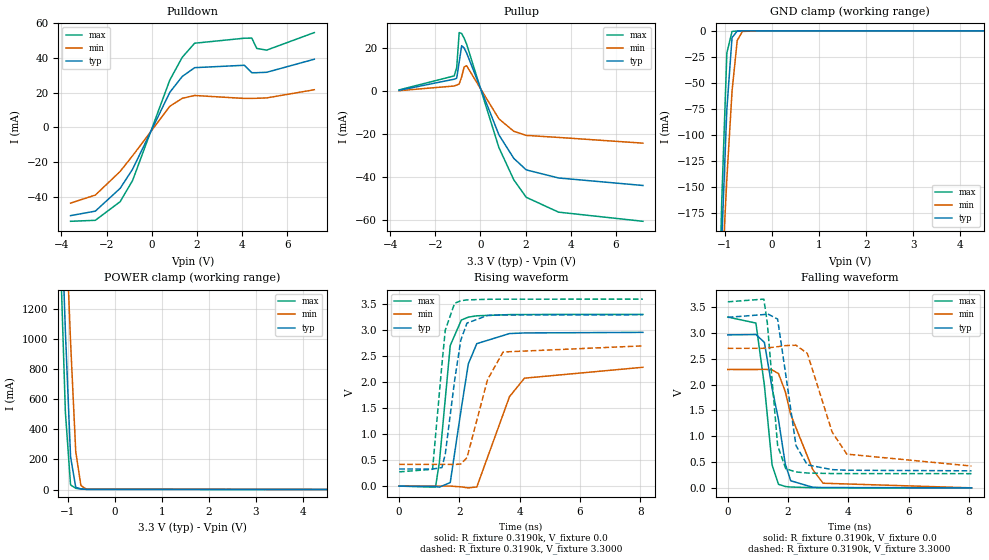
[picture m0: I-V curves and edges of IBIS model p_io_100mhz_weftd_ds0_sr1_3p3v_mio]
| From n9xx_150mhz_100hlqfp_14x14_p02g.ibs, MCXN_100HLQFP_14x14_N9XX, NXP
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[Model] p_io_100mhz_weftd_ds0_sr1_3p3v_mio
|   Model p_io_100mhz_weftd_ds0_sr1_3p3v_mio
| This model was characterised for following simulation conditions:
| External (pad) voltage:
|   - Typ: 3.3V,   - Min: 2.7V,   - Max: 3.6V
| Library cells for typ/min/max conditions are connected as defined below:
|  pad - External Pad
|  ipp_do_lv - Core Input
|  ipp_obe_lv - Output Buffer Enable
|  IOGC - NC
|  REFH3V3 - REFH3V3
|  REFL3V3 - REFL3V3
|  ZI - NC
|  abut_ncal_vddio[1] - vddio
|  abut_ncal_vddio[2] - vddio
|  abut_ncal_vddio[3] - vssio
|  abut_ncal_vddio[4] - vddio
|  abut_ncal_vddio[5] - vddio
|  abut_ncal_vddio[6] - vssio
|  abut_pcal_vddio[1] - vssio
|  abut_pcal_vddio[2] - vssio
|  abut_pcal_vddio[3] - vddio
|  abut_pcal_vddio[4] - vssio
|  abut_pcal_vddio[5] - vssio
|  abut_pcal_vddio[6] - vddio
|  ipp_do_1p8v - ipp_do_1p8v
|  ipp_dse_lv - 0
|  ipp_eftd_lv - NC
|  ipp_ina_mux_vddio - NC
|  ipp_ina_mux_vddio[0] - NC
|  ipp_ina_mux_vddio[1] - NC
|  ipp_ina_r0_vddio - NC
|  ipp_ina_r0a_vddio - NC
|  ipp_ina_r0b_vddio - NC
|  ipp_ina_r0c_vddio - NC
|  ipp_ina_r0d_vddio - NC
|  ipp_ina_r0e_vddio - NC
|  ipp_ina_r0f_vddio - NC
|  ipp_ina_r300_vddio - NC
|  ipp_ina_r300a_vddio - NC
|  ipp_ina_r300b_vddio - NC
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Model_type I/O
Polarity   Non-Inverting
Enable   Active-High
Vinl =   0.9900V
Vinh =   2.3100V
Vmeas =  1.6500V
Cref =   30.0000pF
Rref =   1.0000M
Vref =   3.3000V
C_comp   1.3824pF   1.3233pF   1.4661pF
|C_comp_pullup   0.6932pF   0.7246pF   0.6714pF
|C_comp_pulldown   0.6082pF   0.6609pF   0.5701pF
[Model Spec]
| variable   typ   min   max
Vinh   2.3100V   1.8900V   2.5200V
Vinl   0.9900V   0.8100V   1.0800V
[Temperature Range]   25.0000   0.1250k   -40.0000
[Voltage Range]   3.3000V   2.7000V   3.6000V
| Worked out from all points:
|   slope of the pulldown table from 0 to 0.495 V, typ, clamps not added: 36.8 ohm
|   slope of the pullup table from 0 to 0.495 V, typ, clamps not added: 37.8 ohm
|   GND clamp passes 1 mA (typ) near -0.75 V on its own axis
|   POWER clamp passes 1 mA (typ) near -0.55 V on its own axis
|   rising waveform, R_fixture 0.3190k, V_fixture 0.0: 20-80 % time 437ps typ, 779ps min, 310ps max; typ from 0 V to 2.96 V
|   rising waveform, R_fixture 0.3190k, V_fixture 3.3000: 20-80 % time 419ps typ, 681ps min, 295ps max; typ from 0.33 V to 3.3 V
|   falling waveform, R_fixture 0.3190k, V_fixture 0.0: 20-80 % time 516ps typ, 821ps min, 360ps max; typ from 2.96 V to 0 V
|   falling waveform, R_fixture 0.3190k, V_fixture 3.3000: 20-80 % time 404ps typ, 755ps min, 278ps max; typ from 3.3 V to 0.33 V
[Pulldown]
|Voltage   I(typ)   I(min)   I(max)
-3.6V     -50.99mA   -43.76mA   -54.26mA
-2.5V     -48.39mA   -39.11mA   -53.69mA
-1.4V     -35.22mA   -25.46mA   -42.92mA
-850mV    -24.19mA   -16.4mA    -30.7mA
800mV     20.23mA    12.14mA    27.32mA
1.35V     29.37mA    16.76mA    40.44mA
1.9V      34.45mA    18.38mA    48.57mA
4.1V      35.83mA    16.68mA    51.45mA
4.43V     31.54mA    16.72mA    51.52mA
4.65V     31.54mA    16.77mA    45.56mA
5.09V     31.78mA    16.98mA    44.58mA
7.2V      39.32mA    21.7mA     54.71mA
[Pullup]
|Voltage   I(typ)   I(min)   I(max)
-3.6V     392.3uA    235.2uA    607.2uA
-1.16V    5.571mA    2.41mA     7.094mA
-1.05V    6.017mA    2.857mA    10.99mA
-940mV    13.55mA    3.321mA    27.21mA
-830mV    21.12mA    6.673mA    26.77mA
-720mV    20.02mA    11.25mA    24.57mA
-610mV    17.72mA    11.8mA     21.82mA
820mV     -20.27mA   -12.85mA   -26.19mA
1.48V     -31.2mA    -18.62mA   -41.17mA
2.03V     -36.53mA   -20.52mA   -49.25mA
3.46V     -40.29mA   -21.47mA   -56.15mA
7.2V      -43.77mA   -24.12mA   -60.4mA
[GND_clamp]
|Voltage   I(typ)   I(min)   I(max)
-3.6V     -4.179A    -3.084A    -5.65A
-1.18V    -350.3mA   -344.8mA   -366.5mA
-1.07V    -203.5mA   -240.3mA   -165.6mA
-960mV    -75.17mA   -142.1mA   -21.27mA
-850mV    -6.53mA    -58.02mA   -538.4uA
-740mV    -289.9uA   -9.332mA   -209.1uA
-630mV    -85.04uA   -601.4uA   -92.54uA
-300mV    -199.1nA   -1.25uA    -48.79nA
7.2V      0A         0A         0A
[POWER_clamp]
|Voltage   I(typ)   I(min)   I(max)
-3.6V     24.55A     22.33A     26.93A
-1.16V    2.047A     2.721A     1.599A
-1.05V    1.052A     1.848A     514.6mA
-940mV    218.8mA    982.2mA    31.26mA
-830mV    15.16mA    252.6mA    8.517mA
-720mV    4.307mA    26.88mA    4.483mA
-610mV    1.728mA    3.641mA    1.672mA
7.2V      0A         0A         0A
[Ramp]
| variable   typ   min   max
dV/dt_r  1.7760/0.4371n   1.3726/0.7786n   1.9829/0.3104n
dV/dt_f  1.7821/0.4037n   1.3666/0.7552n   1.9953/0.2777n
R_load = 0.3190k
[Rising Waveform]
R_fixture= 0.3190k
V_fixture= 0.0
V_fixture_min= 0.0
V_fixture_max= 0.0
|time   V(typ)   V(min)   V(max)
0s        3.011nV    251.5nV    9.8nV
1.206ns   -7.511mV   -184.4uV   -19.56mV
1.335ns   -19.5mV    138.1uV    456.6mV
1.696ns   68.92mV    544.4uV    2.707V
2.064ns   1.5V       -15.61mV   3.197V
2.296ns   2.353V     -33.63mV   3.253V
2.577ns   2.743V     -16.96mV   3.279V
3.662ns   2.937V     1.722V     3.302V
4.157ns   2.949V     2.078V     3.304V
8.09ns    2.96V      2.288V     3.305V
[Rising Waveform]
R_fixture= 0.3190k
V_fixture= 3.3000
V_fixture_min= 2.7000
V_fixture_max= 3.6000
|time   V(typ)   V(min)   V(max)
0s        329.6mV    418.3mV    274.4mV
1.109ns   328.4mV    418.1mV    323.9mV
1.421ns   356.6mV    418.8mV    2.35V
1.531ns   616.8mV    419.3mV    3.003V
1.84ns    2.031V     415.3mV    3.519V
2.046ns   2.81V      426.1mV    3.569V
2.251ns   3.138V     546.9mV    3.585V
2.934ns   3.286V     2.051V     3.597V
3.449ns   3.295V     2.582V     3.599V
8.09ns    3.3V       2.7V       3.6V
[Falling Waveform]
R_fixture= 0.3190k
V_fixture= 0.0
V_fixture_min= 0.0
V_fixture_max= 0.0
|time   V(typ)   V(min)   V(max)
0s        2.96V      2.291V     3.305V
933.9ps   2.967V     2.29V      3.189V
1.215ns   2.816V     2.294V     1.987V
1.472ns   1.926V     2.283V     440.3mV
1.683ns   1.32V      2.211V     68.58mV
1.909ns   460.8mV    1.863V     26.48mV
2.089ns   136.9mV    1.417V     16.07mV
2.819ns   11.95mV    356mV      3.255mV
3.162ns   6.365mV    89.73mV    1.766mV
8.09ns    100.7uV    351.8uV    59.33uV
[Falling Waveform]
R_fixture= 0.3190k
V_fixture= 3.3000
V_fixture_min= 2.7000
V_fixture_max= 3.6000
|time   V(typ)   V(min)   V(max)
0s        3.3V       2.7V       3.6V
1.196ns   3.353V     2.701V     3.652V
1.311ns   3.37V      2.707V     3.199V
1.654ns   3.266V     2.732V     820.2mV
1.925ns   2.187V     2.753V     370mV
2.264ns   818mV      2.76V      307.8mV
2.64ns    444.7mV    2.603V     287.7mV
3.465ns   352.8mV    1.077V     277mV
3.95ns    340.7mV    652.7mV    275.7mV
8.09ns    329.9mV    422.3mV    274.5mV
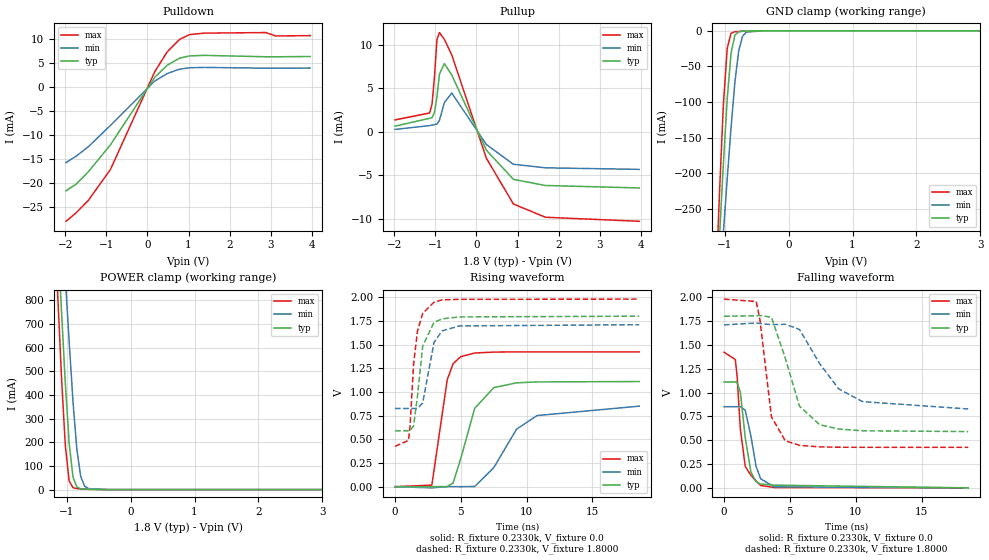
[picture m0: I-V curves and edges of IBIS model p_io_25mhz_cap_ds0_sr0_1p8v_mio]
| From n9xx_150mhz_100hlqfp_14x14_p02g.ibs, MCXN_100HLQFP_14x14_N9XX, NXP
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[Model] p_io_25mhz_cap_ds0_sr0_1p8v_mio
|   Model p_io_25mhz_cap_ds0_sr0_1p8v_mio
| This model was characterised for following simulation conditions:
| External (pad) voltage:
|   - Typ: 1.8V,   - Min: 1.71V,   - Max: 1.98V
| Library cells for typ/min/max conditions are connected as defined below:
|  pad - External Pad
|  ipp_do_lv - Core Input
|  ipp_obe_lv - Output Buffer Enable
|  IOGC - NC
|  REFH3V3 - REFH3V3
|  REFL3V3 - REFL3V3
|  ZI - NC
|  abut_ncal_vddio[1] - vssio vddio vddio
|  abut_ncal_vddio[2] - vddio vddio vssio
|  abut_ncal_vddio[3] - vddio
|  abut_ncal_vddio[4] - vssio vddio vddio
|  abut_ncal_vddio[5] - vddio vddio vssio
|  abut_ncal_vddio[6] - vddio
|  abut_pcal_vddio[1] - vssio
|  abut_pcal_vddio[2] - vddio vssio vddio
|  abut_pcal_vddio[3] - vssio
|  abut_pcal_vddio[4] - vssio
|  abut_pcal_vddio[5] - vddio vssio vddio
|  abut_pcal_vddio[6] - vssio
|  ipp_do_1p8v - ipp_do_1p8v
|  ipp_dse_lv - 0
|  ipp_eftd_lv - NC
|  ipp_ina_mux_vddio - NC
|  ipp_ina_mux_vddio[0] - NC
|  ipp_ina_mux_vddio[1] - NC
|  ipp_ina_r0_vddio - NC
|  ipp_ina_r0a_vddio - NC
|  ipp_ina_r0b_vddio - NC
|  ipp_ina_r0c_vddio - NC
|  ipp_ina_r0d_vddio - NC
|  ipp_ina_r0e_vddio - NC
|  ipp_ina_r0f_vddio - NC
|  ipp_ina_r300_vddio - NC
|  ipp_ina_r300a_vddio - NC
|  ipp_ina_r300b_vddio - NC
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Model_type I/O
Polarity   Non-Inverting
Enable   Active-High
Vinl =   0.5400V
Vinh =   1.2600V
Vmeas =  0.9000V
Cref =   30.0000pF
Rref =   1.0000M
Vref =   1.8000V
C_comp   1.3068pF   1.2541pF   1.3694pF
|C_comp_pullup   0.5696pF   0.5988pF   0.5428pF
|C_comp_pulldown   0.6504pF   0.6822pF   0.6255pF
[Model Spec]
| variable   typ   min   max
Vinh   1.2600V   1.1970V   1.3860V
Vinl   0.5400V   0.5130V   0.5940V
[Temperature Range]   25.0000   0.1250k   -40.0000
[Voltage Range]   1.8000V   1.7100V   1.9800V
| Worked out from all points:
|   slope of the pulldown table from 0 to 0.27 V, typ, clamps not added: 93.6 ohm
|   slope of the pullup table from 0 to 0.27 V, typ, clamps not added: 116 ohm
|   GND clamp passes 1 mA (typ) near -0.76 V on its own axis
|   POWER clamp passes 1 mA (typ) near -0.63 V on its own axis
|   rising waveform, R_fixture 0.2330k, V_fixture 0.0: 20-80 % time 1.45ns typ, 2.43ns min, 833ps max; typ from 0 V to 1.11 V
|   rising waveform, R_fixture 0.2330k, V_fixture 1.8000: 20-80 % time 594ps typ, 656ps min, 564ps max; typ from 0.59 V to 1.8 V
|   falling waveform, R_fixture 0.2330k, V_fixture 0.0: 20-80 % time 571ps typ, 672ps min, 510ps max; typ from 1.11 V to 0 V
|   falling waveform, R_fixture 0.2330k, V_fixture 1.8000: 20-80 % time 1.51ns typ, 2.64ns min, 803ps max; typ from 1.8 V to 0.591 V
[Pulldown]
|Voltage   I(typ)   I(min)   I(max)
-1.98V    -21.59mA   -15.72mA   -27.94mA
-1.74V    -20.25mA   -14.42mA   -26.22mA
-1.44V    -17.66mA   -12.45mA   -23.61mA
-900mV    -12.03mA   -7.993mA   -17.17mA
180mV     2.026mA    1.252mA    3.209mA
480mV     4.533mA    2.805mA    7.305mA
780mV     5.999mA    3.713mA    9.891mA
1.02V     6.469mA    4.005mA    10.9mA
1.38V     6.587mA    4.078mA    11.21mA
2.88V     6.294mA    3.923mA    11.33mA
3.12V     6.289mA    3.924mA    10.62mA
3.96V     6.351mA    3.959mA    10.7mA
[Pullup]
|Voltage   I(typ)   I(min)   I(max)
-1.98V    644.9uA    266.3uA    1.361mA
-1.14V    1.542mA    707.2uA    2.153mA
-1.08V    1.604mA    764.5uA    3.171mA
-1.02V    2.234mA    824.1uA    6.358mA
-960mV    4.021mA    885.3uA    10.59mA
-900mV    6.607mA    1.315mA    11.37mA
-780mV    7.807mA    3.354mA    10.59mA
-600mV    6.505mA    4.443mA    8.805mA
240mV     -2.097mA   -1.459mA   -3.022mA
900mV     -5.454mA   -3.726mA   -8.28mA
1.68V     -6.156mA   -4.132mA   -9.795mA
3.96V     -6.438mA   -4.31mA    -10.26mA
[GND_clamp]
|Voltage   I(typ)   I(min)   I(max)
-1.98V    -2A        -1.65A     -2.499A
-1.14V    -394mA     -441.5mA   -363.8mA
-1.08V    -288.3mA   -361.7mA   -226.5mA
-1.02V    -187.2mA   -283.6mA   -103.8mA
-960mV    -95.64mA   -207.9mA   -24.71mA
-900mV    -31.47mA   -136.2mA   -3.431mA
-840mV    -6.005mA   -72.18mA   -1.326mA
-780mV    -1.297mA   -27.91mA   -902.8uA
-720mV    -576.7uA   -7.631mA   -619.4uA
-660mV    -346.6uA   -1.807mA   -391.2uA
-420mV    -13.9uA    -31.12uA   -8.588uA
3.96V     0A         0A         0A
[POWER_clamp]
|Voltage   I(typ)   I(min)   I(max)
-1.98V    5.618A     5.349A     6.084A
-1.14V    1.071A     1.443A     829.6mA
-1.08V    754.2mA    1.168A     476.4mA
-1.02V    449mA      895.6mA    184.6mA
-960mV    195.8mA    625.5mA    36.79mA
-900mV    52.44mA    371.1mA    7.808mA
-840mV    10.74mA    170.2mA    4.435mA
-780mV    3.619mA    56.22mA    3.182mA
-720mV    2.074mA    15.04mA    2.195mA
-660mV    1.306mA    4.299mA    1.376mA
-360mV    5.079uA    27.62uA    1.341uA
3.96V     0A         0A         0A
[Ramp]
| variable   typ   min   max
dV/dt_r  0.6658/1.4491n   0.5100/2.4250n   0.8537/0.8329n
dV/dt_f  0.7257/1.5108n   0.5293/2.6437n   0.9328/0.8029n
R_load = 0.2330k
[Rising Waveform]
R_fixture= 0.2330k
V_fixture= 0.0
V_fixture_min= 0.0
V_fixture_max= 0.0
|time   V(typ)   V(min)   V(max)
0s        633.2pV    205.5nV    16.75pV
2.795ns   -99.41uV   -12.57mV   16.27mV
3.965ns   1.583mV    445.2uV    1.129V
4.412ns   39.42mV    821.3uV    1.298V
4.991ns   296.3mV    52.54uV    1.373V
6.05ns    827.3mV    1.711mV    1.411V
7.507ns   1.046V     202.2mV    1.421V
9.23ns    1.096V     607.3mV    1.423V
10.79ns   1.106V     750.8mV    1.423V
18.55ns   1.11V      850.1mV    1.423V
[Rising Waveform]
R_fixture= 0.2330k
V_fixture= 1.8000
V_fixture_min= 1.7100
V_fixture_max= 1.9800
|time   V(typ)   V(min)   V(max)
0s        590.5mV    825.5mV    425.3mV
1.016ns   590.4mV    825.6mV    487.9mV
1.134ns   591.4mV    825.6mV    625mV
1.409ns   641.9mV    825.5mV    1.295V
1.698ns   949.9mV    826.7mV    1.637V
2.101ns   1.484V     883.3mV    1.83V
2.955ns   1.734V     1.521V     1.947V
3.57ns    1.772V     1.645V     1.972V
4.906ns   1.792V     1.697V     1.978V
18.55ns   1.8V       1.71V      1.98V
[Falling Waveform]
R_fixture= 0.2330k
V_fixture= 0.0
V_fixture_min= 0.0
V_fixture_max= 0.0
|time   V(typ)   V(min)   V(max)
0s        1.11V      851.6mV    1.423V
854.6ps   1.111V     851.5mV    1.346V
992ps     1.105V     851.6mV    1.167V
1.236ns   1.006V     853.4mV    619.8mV
1.608ns   526.1mV    815.3mV    225.1mV
2.041ns   165.8mV    541.3mV    131mV
2.426ns   64.17mV    230.4mV    73.84mV
2.772ns   40.4mV     95.9mV     24.49mV
3.8ns     28.4mV     10.64mV    4.102mV
18.55ns   312.8nV    11.38uV    55.63nV
[Falling Waveform]
R_fixture= 0.2330k
V_fixture= 1.8000
V_fixture_min= 1.7100
V_fixture_max= 1.9800
|time   V(typ)   V(min)   V(max)
0s        1.8V       1.71V      1.98V
2.442ns   1.806V     1.729V     1.955V
2.725ns   1.809V     1.725V     1.763V
3.6ns     1.79V      1.712V     744.7mV
4.652ns   1.36V      1.716V     493.9mV
5.729ns   856.9mV    1.662V     446.4mV
7.262ns   663mV      1.303V     429.6mV
8.706ns   617.2mV    1.039V     426.4mV
10.52ns   598.6mV    904.5mV    425.5mV
18.55ns   590.6mV    827.8mV    425.3mV
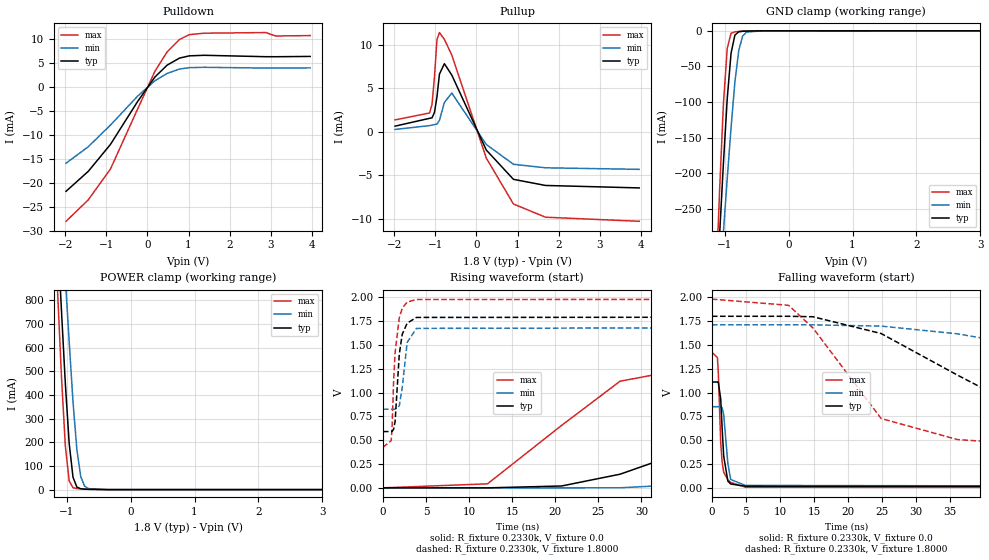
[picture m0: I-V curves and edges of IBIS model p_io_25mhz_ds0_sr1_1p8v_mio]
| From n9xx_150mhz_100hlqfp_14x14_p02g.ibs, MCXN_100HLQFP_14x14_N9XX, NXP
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[Model] p_io_25mhz_ds0_sr1_1p8v_mio
|   Model p_io_25mhz_ds0_sr1_1p8v_mio
| This model was characterised for following simulation conditions:
| External (pad) voltage:
|   - Typ: 1.8V,   - Min: 1.71V,   - Max: 1.98V
| Library cells for typ/min/max conditions are connected as defined below:
|  pad - External Pad
|  ipp_do_lv - Core Input
|  ipp_obe_lv - Output Buffer Enable
|  IOGC - NC
|  REFH3V3 - REFH3V3
|  REFL3V3 - REFL3V3
|  ZI - NC
|  abut_ncal_vddio[1] - vssio vddio vddio
|  abut_ncal_vddio[2] - vddio vddio vssio
|  abut_ncal_vddio[3] - vddio
|  abut_ncal_vddio[4] - vssio vddio vddio
|  abut_ncal_vddio[5] - vddio vddio vssio
|  abut_ncal_vddio[6] - vddio
|  abut_pcal_vddio[1] - vssio
|  abut_pcal_vddio[2] - vddio vssio vddio
|  abut_pcal_vddio[3] - vssio
|  abut_pcal_vddio[4] - vssio
|  abut_pcal_vddio[5] - vddio vssio vddio
|  abut_pcal_vddio[6] - vssio
|  ipp_do_1p8v - ipp_do_1p8v
|  ipp_dse_lv - 0
|  ipp_eftd_lv - NC
|  ipp_ina_mux_vddio - NC
|  ipp_ina_mux_vddio[0] - NC
|  ipp_ina_mux_vddio[1] - NC
|  ipp_ina_r0_vddio - NC
|  ipp_ina_r0a_vddio - NC
|  ipp_ina_r0b_vddio - NC
|  ipp_ina_r0c_vddio - NC
|  ipp_ina_r0d_vddio - NC
|  ipp_ina_r0e_vddio - NC
|  ipp_ina_r0f_vddio - NC
|  ipp_ina_r300_vddio - NC
|  ipp_ina_r300a_vddio - NC
|  ipp_ina_r300b_vddio - NC
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Model_type I/O
Polarity   Non-Inverting
Enable   Active-High
Vinl =   0.5400V
Vinh =   1.2600V
Vmeas =  0.9000V
Cref =   30.0000pF
Rref =   1.0000M
Vref =   1.8000V
C_comp   1.3069pF   1.2545pF   1.3693pF
|C_comp_pullup   0.5685pF   0.5978pF   0.5416pF
|C_comp_pulldown   0.6467pF   0.6778pF   0.6222pF
[Model Spec]
| variable   typ   min   max
Vinh   1.2600V   1.1970V   1.3860V
Vinl   0.5400V   0.5130V   0.5940V
[Temperature Range]   25.0000   0.1250k   -40.0000
[Voltage Range]   1.8000V   1.7100V   1.9800V
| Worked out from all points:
|   slope of the pulldown table from 0 to 0.27 V, typ, clamps not added: 93.6 ohm
|   slope of the pullup table from 0 to 0.27 V, typ, clamps not added: 116 ohm
|   GND clamp passes 1 mA (typ) near -0.75 V on its own axis
|   POWER clamp passes 1 mA (typ) near -0.63 V on its own axis
|   rising waveform, R_fixture 0.2330k, V_fixture 0.0: 20-80 % time 23.5ns typ, 44.3ns min, 11.7ns max; typ from 0 V to 1.11 V
|   rising waveform, R_fixture 0.2330k, V_fixture 1.8000: 20-80 % time 587ps typ, 646ps min, 568ps max; typ from 0.591 V to 1.8 V
|   falling waveform, R_fixture 0.2330k, V_fixture 0.0: 20-80 % time 555ps typ, 639ps min, 507ps max; typ from 1.11 V to 0 V
|   falling waveform, R_fixture 0.2330k, V_fixture 1.8000: 20-80 % time 19.8ns typ, 38.7ns min, 9.78ns max; typ from 1.8 V to 0.591 V
[Pulldown]
|Voltage   I(typ)   I(min)   I(max)
-1.98V    -21.81mA   -15.95mA   -28.07mA
-1.44V    -17.65mA   -12.51mA   -23.6mA
-900mV    -12.03mA   -7.99mA    -17.17mA
-240mV    -3.083mA   -1.961mA   -4.663mA
180mV     2.025mA    1.252mA    3.208mA
480mV     4.532mA    2.805mA    7.302mA
780mV     5.997mA    3.712mA    9.887mA
1.02V     6.467mA    4.004mA    10.9mA
1.38V     6.586mA    4.077mA    11.2mA
2.88V     6.292mA    3.922mA    11.33mA
3.12V     6.287mA    3.924mA    10.62mA
3.96V     6.35mA     3.959mA    10.7mA
[Pullup]
|Voltage   I(typ)   I(min)   I(max)
-1.98V    645.6uA    266.4uA    1.363mA
-1.14V    1.543mA    707.6uA    2.155mA
-1.08V    1.605mA    764.9uA    3.173mA
-1.02V    2.235mA    824.6uA    6.361mA
-960mV    4.023mA    885.7uA    10.59mA
-900mV    6.61mA     1.315mA    11.38mA
-780mV    7.81mA     3.355mA    10.6mA
-600mV    6.507mA    4.444mA    8.808mA
240mV     -2.097mA   -1.459mA   -3.023mA
900mV     -5.456mA   -3.727mA   -8.283mA
1.68V     -6.158mA   -4.133mA   -9.8mA
3.96V     -6.441mA   -4.311mA   -10.27mA
[GND_clamp]
|Voltage   I(typ)   I(min)   I(max)
-1.98V    -1.998A    -1.645A    -2.498A
-1.14V    -394mA     -441.4mA   -363.8mA
-1.08V    -288.3mA   -361.7mA   -226.5mA
-1.02V    -187.2mA   -283.6mA   -103.9mA
-960mV    -95.66mA   -207.9mA   -24.81mA
-900mV    -31.51mA   -136.2mA   -3.524mA
-840mV    -6.042mA   -72.18mA   -1.396mA
-780mV    -1.326mA   -27.91mA   -952.4uA
-720mV    -597.6uA   -7.636mA   -652.9uA
-660mV    -360.6uA   -1.814mA   -412.4uA
-420mV    -15.1uA    -32.81uA   -9.569uA
3.96V     0A         0A         0A
[POWER_clamp]
|Voltage   I(typ)   I(min)   I(max)
-1.98V    5.618A     5.349A     6.084A
-1.14V    1.071A     1.443A     829.5mA
-1.08V    754.2mA    1.168A     476.4mA
-1.02V    449mA      895.6mA    184.5mA
-960mV    195.8mA    625.5mA    36.73mA
-900mV    52.41mA    371.1mA    7.756mA
-840mV    10.72mA    170.2mA    4.398mA
-780mV    3.601mA    56.22mA    3.157mA
-720mV    2.062mA    15.03mA    2.179mA
-660mV    1.299mA    4.293mA    1.367mA
-360mV    5.029uA    27.47uA    1.319uA
3.96V     0A         0A         0A
[Ramp]
| variable   typ   min   max
dV/dt_r  0.6659/23.4664n   0.5079/44.3002n   0.8538/11.7473n
dV/dt_f  0.7255/19.8165n   0.5284/38.7111n   0.9327/9.7810n
R_load = 0.2330k
[Rising Waveform]
R_fixture= 0.2330k
V_fixture= 0.0
V_fixture_min= 0.0
V_fixture_max= 0.0
|time   V(typ)   V(min)   V(max)
0s        678.8pV    209.7nV    17.67pV
12.14ns   -38.6uV    -17.2uV    42.24mV
20.73ns   19.57mV    38.34uV    654.9mV
27.52ns   143.4mV    865.9uV    1.119V
40.92ns   567.4mV    62.22mV    1.345V
49.87ns   819mV      153.7mV    1.384V
60.31ns   959.9mV    289.3mV    1.405V
82.64ns   1.06V      577.1mV    1.419V
103.5ns   1.09V      717.4mV    1.422V
225.6ns   1.11V      846.5mV    1.423V
[Rising Waveform]
R_fixture= 0.2330k
V_fixture= 1.8000
V_fixture_min= 1.7100
V_fixture_max= 1.9800
|time   V(typ)   V(min)   V(max)
0s        590.6mV    825.6mV    425.5mV
964.4ps   590.5mV    825.6mV    494.2mV
1.061ns   590.7mV    825.6mV    608mV
1.25ns    614.7mV    825.7mV    1.12V
1.422ns   697.3mV    825.5mV    1.418V
1.906ns   1.402V     860.3mV    1.785V
2.251ns   1.612V     1.054V     1.884V
2.823ns   1.728V     1.526V     1.95V
3.894ns   1.788V     1.673V     1.976V
225.6ns   1.8V       1.71V      1.98V
[Falling Waveform]
R_fixture= 0.2330k
V_fixture= 0.0
V_fixture_min= 0.0
V_fixture_max= 0.0
|time   V(typ)   V(min)   V(max)
0s        1.11V      851.8mV    1.423V
819.8ps   1.111V     851.7mV    1.366V
942.4ps   1.11V      851.6mV    1.216V
1.302ns   931mV      853.7mV    470.9mV
1.506ns   628.6mV    840.2mV    270.5mV
1.739ns   333.3mV    767.3mV    164.3mV
2.346ns   71.3mV     258.7mV    85.52mV
2.764ns   40.48mV    88.23mV    57.04mV
4.934ns   17.59mV    25.41mV    6.492mV
225.6ns   177.9nV    2.92uV     35.24nV
[Falling Waveform]
R_fixture= 0.2330k
V_fixture= 1.8000
V_fixture_min= 1.7100
V_fixture_max= 1.9800
|time   V(typ)   V(min)   V(max)
0s        1.8V       1.71V      1.98V
11.28ns   1.8V       1.71V      1.915V
14.86ns   1.795V     1.71V      1.677V
24.88ns   1.619V     1.697V     727.4mV
36.09ns   1.183V     1.616V     506.8mV
43.89ns   892.9mV    1.52V      469.2mV
52.23ns   754.2mV    1.391V     449.7mV
71.1ns    651.9mV    1.097V     432.6mV
92.27ns   615.1mV    950.3mV    427.4mV
225.6ns   590.8mV    829.3mV    425.5mV
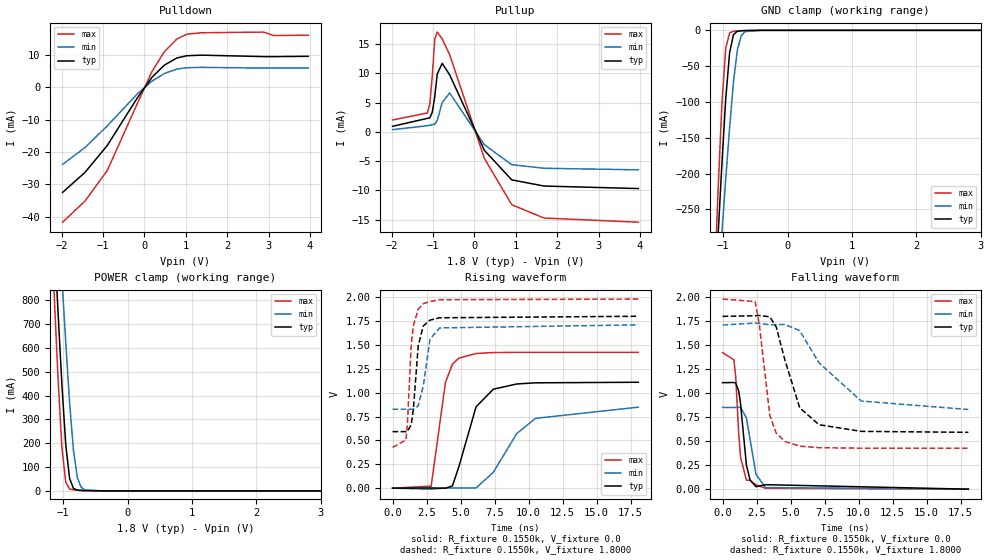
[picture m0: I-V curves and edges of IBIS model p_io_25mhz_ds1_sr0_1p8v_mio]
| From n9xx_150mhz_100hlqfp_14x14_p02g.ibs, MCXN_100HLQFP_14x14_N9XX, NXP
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[Model] p_io_25mhz_ds1_sr0_1p8v_mio
|   Model p_io_25mhz_ds1_sr0_1p8v_mio
| This model was characterised for following simulation conditions:
| External (pad) voltage:
|   - Typ: 1.8V,   - Min: 1.71V,   - Max: 1.98V
| Library cells for typ/min/max conditions are connected as defined below:
|  pad - External Pad
|  ipp_do_lv - Core Input
|  ipp_obe_lv - Output Buffer Enable
|  IOGC - NC
|  REFH3V3 - REFH3V3
|  REFL3V3 - REFL3V3
|  ZI - NC
|  abut_ncal_vddio[1] - vssio vddio vddio
|  abut_ncal_vddio[2] - vddio vddio vssio
|  abut_ncal_vddio[3] - vddio
|  abut_ncal_vddio[4] - vssio vddio vddio
|  abut_ncal_vddio[5] - vddio vddio vssio
|  abut_ncal_vddio[6] - vddio
|  abut_pcal_vddio[1] - vssio
|  abut_pcal_vddio[2] - vddio vssio vddio
|  abut_pcal_vddio[3] - vssio
|  abut_pcal_vddio[4] - vssio
|  abut_pcal_vddio[5] - vddio vssio vddio
|  abut_pcal_vddio[6] - vssio
|  ipp_do_1p8v - ipp_do_1p8v
|  ipp_dse_lv - vdd_lv
|  ipp_eftd_lv - NC
|  ipp_ina_mux_vddio - NC
|  ipp_ina_mux_vddio[0] - NC
|  ipp_ina_mux_vddio[1] - NC
|  ipp_ina_r0_vddio - NC
|  ipp_ina_r0a_vddio - NC
|  ipp_ina_r0b_vddio - NC
|  ipp_ina_r0c_vddio - NC
|  ipp_ina_r0d_vddio - NC
|  ipp_ina_r0e_vddio - NC
|  ipp_ina_r0f_vddio - NC
|  ipp_ina_r300_vddio - NC
|  ipp_ina_r300a_vddio - NC
|  ipp_ina_r300b_vddio - NC
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Model_type I/O
Polarity   Non-Inverting
Enable   Active-High
Vinl =   0.5400V
Vinh =   1.2600V
Vmeas =  0.9000V
Cref =   30.0000pF
Rref =   1.0000M
Vref =   1.8000V
C_comp   1.3069pF   1.2545pF   1.3693pF
|C_comp_pullup   0.5683pF   0.5976pF   0.5414pF
|C_comp_pulldown   0.6468pF   0.6780pF   0.6224pF
[Model Spec]
| variable   typ   min   max
Vinh   1.2600V   1.1970V   1.3860V
Vinl   0.5400V   0.5130V   0.5940V
[Temperature Range]   25.0000   0.1250k   -40.0000
[Voltage Range]   1.8000V   1.7100V   1.9800V
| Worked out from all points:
|   slope of the pulldown table from 0 to 0.27 V, typ, clamps not added: 62.4 ohm
|   slope of the pullup table from 0 to 0.27 V, typ, clamps not added: 77.5 ohm
|   GND clamp passes 1 mA (typ) near -0.75 V on its own axis
|   POWER clamp passes 1 mA (typ) near -0.63 V on its own axis
|   rising waveform, R_fixture 0.1550k, V_fixture 0.0: 20-80 % time 1.4ns typ, 2.48ns min, 787ps max; typ from 0 V to 1.11 V
|   rising waveform, R_fixture 0.1550k, V_fixture 1.8000: 20-80 % time 420ps typ, 518ps min, 382ps max; typ from 0.592 V to 1.8 V
|   falling waveform, R_fixture 0.1550k, V_fixture 0.0: 20-80 % time 459ps typ, 585ps min, 378ps max; typ from 1.11 V to 0 V
|   falling waveform, R_fixture 0.1550k, V_fixture 1.8000: 20-80 % time 1.51ns typ, 2.68ns min, 780ps max; typ from 1.8 V to 0.592 V
[Pulldown]
|Voltage   I(typ)   I(min)   I(max)
-1.98V    -32.47mA   -23.82mA   -41.66mA
-1.44V    -26.32mA   -18.64mA   -35.17mA
-900mV    -18mA      -11.95mA   -25.72mA
-180mV    -3.436mA   -2.171mA   -5.242mA
180mV     3.037mA    1.878mA    4.808mA
480mV     6.796mA    4.207mA    10.95mA
780mV     8.996mA    5.568mA    14.83mA
1.02V     9.701mA    6.008mA    16.34mA
1.38V     9.88mA     6.118mA    16.8mA
2.88V     9.438mA    5.883mA    17mA
3.12V     9.431mA    5.886mA    15.93mA
3.96V     9.527mA    5.94mA     16.05mA
[Pullup]
|Voltage   I(typ)   I(min)   I(max)
-1.98V    967.4uA    399.6uA    2.046mA
-1.14V    2.322mA    1.064mA    3.245mA
-1.08V    2.417mA    1.15mA     4.767mA
-1.02V    3.36mA     1.241mA    9.562mA
-960mV    6.043mA    1.333mA    15.9mA
-900mV    9.924mA    1.975mA    17.07mA
-780mV    11.72mA    5.036mA    15.9mA
-600mV    9.761mA    6.668mA    13.21mA
240mV     -3.146mA   -2.19mA    -4.535mA
900mV     -8.187mA   -5.593mA   -12.43mA
1.68V     -9.242mA   -6.203mA   -14.71mA
3.96V     -9.672mA   -6.474mA   -15.42mA
[GND_clamp]
|Voltage   I(typ)   I(min)   I(max)
-1.98V    -1.998A    -1.645A    -2.498A
-1.14V    -394mA     -441.4mA   -363.8mA
-1.08V    -288.3mA   -361.7mA   -226.5mA
-1.02V    -187.2mA   -283.6mA   -103.9mA
-960mV    -95.66mA   -207.9mA   -24.8mA
-900mV    -31.51mA   -136.2mA   -3.52mA
-840mV    -6.042mA   -72.18mA   -1.393mA
-780mV    -1.326mA   -27.91mA   -950.1uA
-720mV    -597.6uA   -7.636mA   -651.3uA
-660mV    -360.6uA   -1.814mA   -411.4uA
-420mV    -15.1uA    -32.81uA   -9.558uA
3.96V     0A         0A         0A
[POWER_clamp]
|Voltage   I(typ)   I(min)   I(max)
-1.98V    5.618A     5.349A     6.084A
-1.14V    1.071A     1.443A     829.5mA
-1.08V    754.2mA    1.168A     476.4mA
-1.02V    449mA      895.6mA    184.5mA
-960mV    195.8mA    625.5mA    36.73mA
-900mV    52.41mA    371.1mA    7.756mA
-840mV    10.72mA    170.2mA    4.398mA
-780mV    3.601mA    56.22mA    3.157mA
-720mV    2.062mA    15.03mA    2.179mA
-660mV    1.299mA    4.293mA    1.367mA
-360mV    5.029uA    27.47uA    1.319uA
3.96V     0A         0A         0A
[Ramp]
| variable   typ   min   max
dV/dt_r  0.6653/1.3988n   0.5089/2.4782n   0.8533/0.7870n
dV/dt_f  0.7248/1.5112n   0.5282/2.6833n   0.9320/0.7799n
R_load = 0.1550k
[Rising Waveform]
R_fixture= 0.1550k
V_fixture= 0.0
V_fixture_min= 0.0
V_fixture_max= 0.0
|time   V(typ)   V(min)   V(max)
0s        479.1pV    140.6nV    13.08pV
2.836ns   2.19mV     -10.44mV   21.14mV
3.886ns   -132.3uV   1.693mV    1.106V
4.397ns   23.28mV    1.589mV    1.299V
4.881ns   228.9mV    779.5uV    1.362V
6.135ns   851.8mV    2.486mV    1.41V
7.403ns   1.036V     166mV      1.42V
9.124ns   1.091V     571.3mV    1.422V
10.5ns    1.103V     730.9mV    1.422V
18.06ns   1.109V     848.2mV    1.422V
[Rising Waveform]
R_fixture= 0.1550k
V_fixture= 1.8000
V_fixture_min= 1.7100
V_fixture_max= 1.9800
|time   V(typ)   V(min)   V(max)
0s        591.9mV    826.9mV    426.6mV
978.6ps   591.6mV    826.9mV    504mV
1.089ns   593.4mV    826.9mV    666.1mV
1.364ns   663.2mV    826.9mV    1.484V
1.524ns   818.1mV    826.7mV    1.698V
1.885ns   1.491V     862mV      1.874V
2.257ns   1.698V     1.07V      1.931V
2.756ns   1.76V      1.562V     1.954V
3.459ns   1.784V     1.678V     1.973V
18.06ns   1.8V       1.71V      1.98V
[Falling Waveform]
R_fixture= 0.1550k
V_fixture= 0.0
V_fixture_min= 0.0
V_fixture_max= 0.0
|time   V(typ)   V(min)   V(max)
0s        1.109V     850.8mV    1.422V
829.4ps   1.111V     850.7mV    1.348V
965.2ps   1.106V     850.8mV    1.173V
1.19ns    1.02V      852.9mV    572.4mV
1.32ns    892.6mV    853.3mV    332.5mV
1.751ns   250.9mV    743mV      93.39mV
2.024ns   93.94mV    516.6mV    93.24mV
2.455ns   25.61mV    154.5mV    44.97mV
3.157ns   46.81mV    16.63mV    8.945mV
18.06ns   381.6nV    14.42uV    14.69nV
[Falling Waveform]
R_fixture= 0.1550k
V_fixture= 1.8000
V_fixture_min= 1.7100
V_fixture_max= 1.9800
|time   V(typ)   V(min)   V(max)
0s        1.8V       1.71V      1.98V
2.395ns   1.806V     1.73V      1.954V
2.692ns   1.809V     1.726V     1.725V
3.472ns   1.795V     1.712V     768mV
3.94ns    1.691V     1.715V     584.3mV
4.578ns   1.346V     1.715V     497.2mV
5.668ns   847.9mV    1.652V     448.3mV
7.086ns   671.3mV    1.316V     431.8mV
10.19ns   601.9mV    917.9mV    426.9mV
18.06ns   592mV      829.7mV    426.6mV
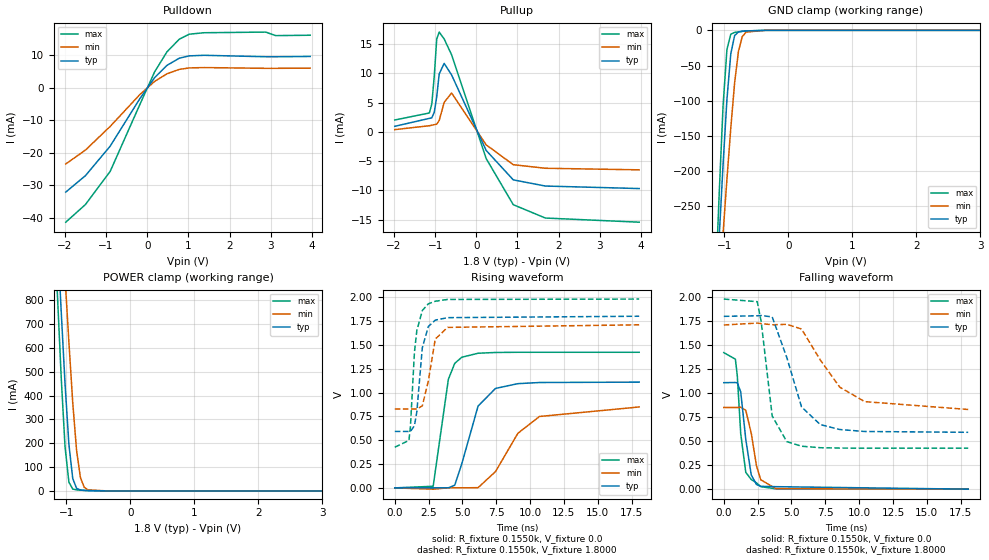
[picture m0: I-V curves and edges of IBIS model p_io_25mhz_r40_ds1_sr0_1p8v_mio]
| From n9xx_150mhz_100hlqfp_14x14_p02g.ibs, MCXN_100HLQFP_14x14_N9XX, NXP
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[Model] p_io_25mhz_r40_ds1_sr0_1p8v_mio
|   Model p_io_25mhz_r40_ds1_sr0_1p8v_mio
| This model was characterised for following simulation conditions:
| External (pad) voltage:
|   - Typ: 1.8V,   - Min: 1.71V,   - Max: 1.98V
| Library cells for typ/min/max conditions are connected as defined below:
|  pad - External Pad
|  ipp_do_lv - Core Input
|  ipp_obe_lv - Output Buffer Enable
|  IOGC - NC
|  REFH3V3 - REFH3V3
|  REFL3V3 - REFL3V3
|  ZI - NC
|  abut_ncal_vddio[1] - vssio vddio vddio
|  abut_ncal_vddio[2] - vddio vddio vssio
|  abut_ncal_vddio[3] - vddio
|  abut_ncal_vddio[4] - vssio vddio vddio
|  abut_ncal_vddio[5] - vddio vddio vssio
|  abut_ncal_vddio[6] - vddio
|  abut_pcal_vddio[1] - vssio
|  abut_pcal_vddio[2] - vddio vssio vddio
|  abut_pcal_vddio[3] - vssio
|  abut_pcal_vddio[4] - vssio
|  abut_pcal_vddio[5] - vddio vssio vddio
|  abut_pcal_vddio[6] - vssio
|  ipp_do_1p8v - ipp_do_1p8v
|  ipp_dse_lv - vdd_lv
|  ipp_eftd_lv - NC
|  ipp_ina_mux_vddio - NC
|  ipp_ina_mux_vddio[0] - NC
|  ipp_ina_mux_vddio[1] - NC
|  ipp_ina_r0_vddio - NC
|  ipp_ina_r0a_vddio - NC
|  ipp_ina_r0b_vddio - NC
|  ipp_ina_r0c_vddio - NC
|  ipp_ina_r0d_vddio - NC
|  ipp_ina_r0e_vddio - NC
|  ipp_ina_r0f_vddio - NC
|  ipp_ina_r300_vddio - NC
|  ipp_ina_r300a_vddio - NC
|  ipp_ina_r300b_vddio - NC
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Model_type I/O
Polarity   Non-Inverting
Enable   Active-High
Vinl =   0.5400V
Vinh =   1.2600V
Vmeas =  0.9000V
Cref =   30.0000pF
Rref =   1.0000M
Vref =   1.8000V
C_comp   1.7117pF   1.6504pF   1.7864pF
|C_comp_pullup   0.6270pF   0.6561pF   0.6003pF
|C_comp_pulldown   0.8236pF   0.8669pF   0.7905pF
[Model Spec]
| variable   typ   min   max
Vinh   1.2600V   1.1970V   1.3860V
Vinl   0.5400V   0.5130V   0.5940V
[Temperature Range]   25.0000   0.1250k   -40.0000
[Voltage Range]   1.8000V   1.7100V   1.9800V
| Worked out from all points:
|   slope of the pulldown table from 0 to 0.27 V, typ, clamps not added: 62.5 ohm
|   slope of the pullup table from 0 to 0.27 V, typ, clamps not added: 77.5 ohm
|   GND clamp passes 1 mA (typ) near -0.68 V on its own axis
|   POWER clamp passes 1 mA (typ) near -0.63 V on its own axis
|   rising waveform, R_fixture 0.1550k, V_fixture 0.0: 20-80 % time 1.37ns typ, 2.4ns min, 780ps max; typ from 0 V to 1.11 V
|   rising waveform, R_fixture 0.1550k, V_fixture 1.8000: 20-80 % time 493ps typ, 575ps min, 460ps max; typ from 0.592 V to 1.8 V
|   falling waveform, R_fixture 0.1550k, V_fixture 0.0: 20-80 % time 517ps typ, 628ps min, 447ps max; typ from 1.11 V to 0 V
|   falling waveform, R_fixture 0.1550k, V_fixture 1.8000: 20-80 % time 1.5ns typ, 2.63ns min, 787ps max; typ from 1.8 V to 0.592 V
[Pulldown]
|Voltage   I(typ)   I(min)   I(max)
-1.98V    -32.06mA   -23.44mA   -41.28mA
-1.5V     -27mA      -19.16mA   -35.85mA
-900mV    -17.97mA   -11.92mA   -25.7mA
-180mV    -3.435mA   -2.171mA   -5.239mA
180mV     3.035mA    1.877mA    4.805mA
480mV     6.794mA    4.206mA    10.94mA
780mV     8.992mA    5.567mA    14.82mA
1.02V     9.698mA    6.006mA    16.34mA
1.38V     9.876mA    6.116mA    16.79mA
2.88V     9.432mA    5.88mA     16.99mA
3.12V     9.425mA    5.883mA    15.91mA
3.96V     9.519mA    5.936mA    16.03mA
[Pullup]
|Voltage   I(typ)   I(min)   I(max)
-1.98V    967.3uA    399.6uA    2.046mA
-1.14V    2.322mA    1.064mA    3.245mA
-1.08V    2.417mA    1.15mA     4.767mA
-1.02V    3.36mA     1.241mA    9.562mA
-960mV    6.043mA    1.333mA    15.9mA
-900mV    9.924mA    1.975mA    17.07mA
-780mV    11.72mA    5.036mA    15.9mA
-600mV    9.761mA    6.668mA    13.21mA
240mV     -3.146mA   -2.19mA    -4.535mA
900mV     -8.187mA   -5.593mA   -12.43mA
1.68V     -9.242mA   -6.203mA   -14.71mA
3.96V     -9.671mA   -6.472mA   -15.42mA
[GND_clamp]
|Voltage   I(typ)   I(min)   I(max)
-1.98V    -2.014A    -1.664A    -2.513A
-1.14V    -398mA     -446.7mA   -367.4mA
-1.08V    -291.8mA   -366.3mA   -229.6mA
-1.02V    -190.1mA   -287.6mA   -106.6mA
-960mV    -98.09mA   -211.4mA   -27.19mA
-900mV    -33.41mA   -139.1mA   -5.497mA
-840mV    -7.43mA    -74.57mA   -2.952mA
-780mV    -2.331mA   -29.72mA   -2.122mA
-720mV    -1.309mA   -8.82mA    -1.477mA
-660mV    -833.8uA   -2.501mA   -940.4uA
-360mV    -6.03uA    -22.55uA   -2.113uA
3.96V     0A         0A         0A
[POWER_clamp]
|Voltage   I(typ)   I(min)   I(max)
-1.98V    5.618A     5.349A     6.084A
-1.14V    1.071A     1.443A     829.6mA
-1.08V    754.2mA    1.168A     476.4mA
-1.02V    449mA      895.6mA    184.6mA
-960mV    195.8mA    625.5mA    36.79mA
-900mV    52.44mA    371.1mA    7.808mA
-840mV    10.74mA    170.2mA    4.435mA
-780mV    3.619mA    56.22mA    3.182mA
-720mV    2.074mA    15.04mA    2.195mA
-660mV    1.306mA    4.299mA    1.376mA
-360mV    5.079uA    27.62uA    1.341uA
3.96V     0A         0A         0A
[Ramp]
| variable   typ   min   max
dV/dt_r  0.6653/1.3677n   0.5092/2.3984n   0.8533/0.7795n
dV/dt_f  0.7247/1.4952n   0.5281/2.6255n   0.9319/0.7871n
R_load = 0.1550k
[Rising Waveform]
R_fixture= 0.1550k
V_fixture= 0.0
V_fixture_min= 0.0
V_fixture_max= 0.0
|time   V(typ)   V(min)   V(max)
0s        440.4pV    137.5nV    11.97pV
2.837ns   552uV      -13.38mV   16.97mV
3.96ns    955.6uV    651.1uV    1.139V
4.431ns   27.95mV    1.038mV    1.306V
4.952ns   252.6mV    481.3uV    1.37V
6.157ns   858.7mV    2.378mV    1.412V
7.445ns   1.043V     171.4mV    1.42V
9.097ns   1.093V     572.5mV    1.422V
10.69ns   1.105V     748.7mV    1.422V
18.06ns   1.109V     848.6mV    1.422V
[Rising Waveform]
R_fixture= 0.1550k
V_fixture= 1.8000
V_fixture_min= 1.7100
V_fixture_max= 1.9800
|time   V(typ)   V(min)   V(max)
0s        592.1mV    827.1mV    426.8mV
1.046ns   591.9mV    827.2mV    497.7mV
1.158ns   592.9mV    827.2mV    644mV
1.453ns   652.1mV    827.1mV    1.421V
1.627ns   795.4mV    826.9mV    1.647V
2.036ns   1.47V      860.3mV    1.86V
2.479ns   1.692V     1.121V     1.93V
2.992ns   1.759V     1.56V      1.957V
3.902ns   1.785V     1.683V     1.976V
18.06ns   1.8V       1.71V      1.98V
[Falling Waveform]
R_fixture= 0.1550k
V_fixture= 0.0
V_fixture_min= 0.0
V_fixture_max= 0.0
|time   V(typ)   V(min)   V(max)
0s        1.109V     850.8mV    1.422V
857.6ps   1.111V     850.8mV    1.354V
999.7ps   1.107V     850.9mV    1.179V
1.252ns   1.013V     852.9mV    576.1mV
1.625ns   517.5mV    822.3mV    174.9mV
2.03ns    147.5mV    580.9mV    100.6mV
2.419ns   47.92mV    241mV      65.39mV
2.73ns    29.58mV    97.96mV    26.28mV
3.835ns   26.02mV    6.353mV    3.823mV
18.06ns   339.5nV    13.3uV     28.91nV
[Falling Waveform]
R_fixture= 0.1550k
V_fixture= 1.8000
V_fixture_min= 1.7100
V_fixture_max= 1.9800
|time   V(typ)   V(min)   V(max)
0s        1.8V       1.71V      1.98V
2.472ns   1.806V     1.73V      1.953V
2.759ns   1.809V     1.725V     1.748V
3.577ns   1.794V     1.712V     762mV
4.654ns   1.372V     1.717V     495.4mV
5.744ns   856.6mV    1.668V     447.4mV
7.127ns   672.8mV    1.346V     431.7mV
8.564ns   621.2mV    1.063V     428mV
10.41ns   600.7mV    911.7mV    427mV
18.06ns   592.2mV    829.8mV    426.8mV
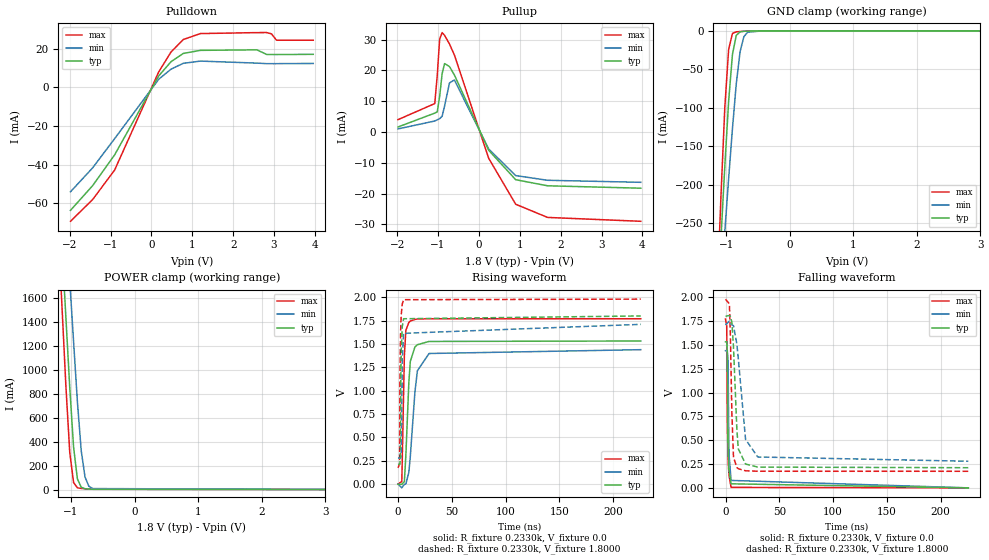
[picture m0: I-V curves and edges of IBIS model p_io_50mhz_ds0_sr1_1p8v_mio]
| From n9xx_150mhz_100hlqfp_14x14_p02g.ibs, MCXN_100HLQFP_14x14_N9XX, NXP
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[Model] p_io_50mhz_ds0_sr1_1p8v_mio
|   Model p_io_50mhz_ds0_sr1_1p8v_mio
| This model was characterised for following simulation conditions:
| External (pad) voltage:
|   - Typ: 1.8V,   - Min: 1.71V,   - Max: 1.98V
| Library cells for typ/min/max conditions are connected as defined below:
|  pad - External Pad
|  ipp_do_lv - Core Input
|  ipp_obe_lv - Output Buffer Enable
|  IOGC - NC
|  REFH3V3 - REFH3V3
|  REFL3V3 - REFL3V3
|  ZI - NC
|  abut_ncal_vddio[1] - vssio vddio vddio
|  abut_ncal_vddio[2] - vddio vddio vssio
|  abut_ncal_vddio[3] - vddio
|  abut_ncal_vddio[4] - vssio vddio vddio
|  abut_ncal_vddio[5] - vddio vddio vssio
|  abut_ncal_vddio[6] - vddio
|  abut_pcal_vddio[1] - vssio
|  abut_pcal_vddio[2] - vddio vssio vddio
|  abut_pcal_vddio[3] - vssio
|  abut_pcal_vddio[4] - vssio
|  abut_pcal_vddio[5] - vddio vssio vddio
|  abut_pcal_vddio[6] - vssio
|  ipp_do_1p8v - ipp_do_1p8v
|  ipp_dse_lv - 0
|  ipp_eftd_lv - NC
|  ipp_ina_mux_vddio - NC
|  ipp_ina_mux_vddio[0] - NC
|  ipp_ina_mux_vddio[1] - NC
|  ipp_ina_r0_vddio - NC
|  ipp_ina_r0a_vddio - NC
|  ipp_ina_r0b_vddio - NC
|  ipp_ina_r0c_vddio - NC
|  ipp_ina_r0d_vddio - NC
|  ipp_ina_r0e_vddio - NC
|  ipp_ina_r0f_vddio - NC
|  ipp_ina_r300_vddio - NC
|  ipp_ina_r300a_vddio - NC
|  ipp_ina_r300b_vddio - NC
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Model_type I/O
Polarity   Non-Inverting
Enable   Active-High
Vinl =   0.5400V
Vinh =   1.2600V
Vmeas =  0.9000V
Cref =   30.0000pF
Rref =   1.0000M
Vref =   1.8000V
C_comp   1.4770pF   1.4118pF   1.5590pF
|C_comp_pullup   0.7601pF   0.7866pF   0.7341pF
|C_comp_pulldown   0.6309pF   0.6843pF   0.5886pF
[Model Spec]
| variable   typ   min   max
Vinh   1.2600V   1.1970V   1.3860V
Vinl   0.5400V   0.5130V   0.5940V
[Temperature Range]   25.0000   0.1250k   -40.0000
[Voltage Range]   1.8000V   1.7100V   1.9800V
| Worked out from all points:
|   slope of the pulldown table from 0 to 0.27 V, typ, clamps not added: 32.1 ohm
|   slope of the pullup table from 0 to 0.27 V, typ, clamps not added: 40.9 ohm
|   GND clamp passes 1 mA (typ) near -0.75 V on its own axis
|   POWER clamp passes 1 mA (typ) near -0.55 V on its own axis
|   rising waveform, R_fixture 0.2330k, V_fixture 0.0: 20-80 % time 3.45ns typ, 5.78ns min, 1.79ns max; typ from 0 V to 1.53 V
|   rising waveform, R_fixture 0.2330k, V_fixture 1.8000: 20-80 % time 855ps typ, 878ps min, 850ps max; typ from 0.211 V to 1.8 V
|   falling waveform, R_fixture 0.2330k, V_fixture 0.0: 20-80 % time 941ps typ, 923ps min, 919ps max; typ from 1.53 V to 0 V
|   falling waveform, R_fixture 0.2330k, V_fixture 1.8000: 20-80 % time 3.54ns typ, 6.49ns min, 1.94ns max; typ from 1.8 V to 0.211 V
[Pulldown]
|Voltage   I(typ)   I(min)   I(max)
-1.98V    -63.59mA   -54.01mA   -69.25mA
-1.44V    -50.89mA   -41.69mA   -58.07mA
-900mV    -34.94mA   -26.56mA   -42.8mA
180mV     5.908mA    4.185mA    8.001mA
480mV     13.23mA    9.376mA    18.23mA
780mV     17.5mA     12.4mA     24.7mA
1.2V      19.1mA     13.55mA    27.77mA
2.58V     19.36mA    12.5mA     28.27mA
2.82V     16.99mA    12.23mA    28.29mA
2.94V     16.93mA    12.23mA    27.6mA
3.06V     16.92mA    12.23mA    24.35mA
3.96V     17.05mA    12.32mA    24.33mA
[Pullup]
|Voltage   I(typ)   I(min)   I(max)
-1.98V    1.62mA     998.6uA    4.005mA
-1.08V    6.133mA    3.566mA    9.235mA
-1.02V    6.531mA    3.947mA    18.33mA
-960mV    11.63mA    4.346mA    30.19mA
-900mV    18.95mA    5.088mA    32.31mA
-840mV    22.23mA    8.438mA    31.4mA
-720mV    21.25mA    15.95mA    28.6mA
-600mV    18.53mA    16.91mA    25.01mA
240mV     -5.967mA   -5.552mA   -8.574mA
900mV     -15.51mA   -14.17mA   -23.49mA
1.68V     -17.49mA   -15.7mA    -27.77mA
3.96V     -18.27mA   -16.36mA   -29.03mA
[GND_clamp]
|Voltage   I(typ)   I(min)   I(max)
-1.98V    -1.861A    -1.524A    -2.333A
-1.14V    -366mA     -404.8mA   -340.6mA
-1.08V    -268.7mA   -331.9mA   -213.6mA
-1.02V    -175.9mA   -260.7mA   -99.6mA
-960mV    -91.54mA   -192mA     -24.26mA
-900mV    -30.77mA   -127.1mA   -3.427mA
-840mV    -5.96mA    -68.91mA   -1.333mA
-780mV    -1.308mA   -27.16mA   -912.6uA
-720mV    -590.1uA   -7.525mA   -632.8uA
-660mV    -358.7uA   -1.804mA   -405.8uA
-420mV    -15.5uA    -34.36uA   -9.86uA
3.96V     0A         0A         0A
[POWER_clamp]
|Voltage   I(typ)   I(min)   I(max)
-1.98V    10.29A     9.986A     10.79A
-1.2V     2.598A     3.277A     2.158A
-1.14V    2.012A     2.764A     1.504A
-1.08V    1.429A     2.253A     855.2mA
-1.02V    851mA      1.743A     310.4mA
-960mV    354.2mA    1.236A     58.61mA
-900mV    89.61mA    734.2mA    15.24mA
-840mV    19.5mA     326mA      9.554mA
-780mV    7.508mA    104.4mA    6.926mA
-720mV    4.523mA    28.33mA    4.778mA
-660mV    2.875mA    8.601mA    2.988mA
3.96V     0A         0A         0A
[Ramp]
| variable   typ   min   max
dV/dt_r  0.9192/3.4510n   0.8633/5.7795n   1.0620/1.7856n
dV/dt_f  0.9532/3.5371n   0.8586/6.4921n   1.0837/1.9388n
R_load = 0.2330k
[Rising Waveform]
R_fixture= 0.2330k
V_fixture= 0.0
V_fixture_min= 0.0
V_fixture_max= 0.0
|time   V(typ)   V(min)   V(max)
0s        540.8pV    177.8nV    14.77pV
3.557ns   -2.018mV   -40.05mV   28.08mV
5.94ns    27.83mV    -2.309mV   1.381V
7.338ns   312.7mV    2.529mV    1.647V
10.07ns   1.083V     124.8mV    1.73V
11.45ns   1.313V     295.2mV    1.745V
15.72ns   1.467V     982.8mV    1.763V
18.02ns   1.492V     1.213V     1.767V
28.87ns   1.527V     1.398V     1.77V
225.6ns   1.532V     1.439V     1.77V
[Rising Waveform]
R_fixture= 0.2330k
V_fixture= 1.8000
V_fixture_min= 1.7100
V_fixture_max= 1.9800
|time   V(typ)   V(min)   V(max)
0s        211.3mV    278.9mV    173.9mV
1.44ns    211.8mV    278.9mV    214.8mV
1.745ns   209.5mV    278.9mV    991.2mV
2.074ns   251.9mV    279.3mV    1.367V
2.208ns   366.6mV    279.2mV    1.478V
2.513ns   1.041V     277.7mV    1.654V
3.02ns    1.43V      312.7mV    1.814V
3.973ns   1.687V     1.311V     1.929V
5.186ns   1.77V      1.614V     1.974V
225.6ns   1.8V       1.71V      1.98V
[Falling Waveform]
R_fixture= 0.2330k
V_fixture= 0.0
V_fixture_min= 0.0
V_fixture_max= 0.0
|time   V(typ)   V(min)   V(max)
0s        1.532V     1.439V     1.77V
1.126ns   1.534V     1.439V     1.702V
1.237ns   1.532V     1.439V     1.584V
1.651ns   1.406V     1.441V     718.2mV
2.283ns   494.2mV    1.352V     334.8mV
2.525ns   368.4mV    1.174V     263.2mV
2.957ns   245mV      586.2mV    177.1mV
3.332ns   177mV      339.5mV    126.5mV
5.207ns   42.37mV    78.06mV    5.004mV
225.6ns   1.215uV    2.531uV    767.6nV
[Falling Waveform]
R_fixture= 0.2330k
V_fixture= 1.8000
V_fixture_min= 1.7100
V_fixture_max= 1.9800
|time   V(typ)   V(min)   V(max)
0s        1.8V       1.71V      1.98V
3.626ns   1.808V     1.75V      1.928V
4.507ns   1.799V     1.722V     1.608V
5.911ns   1.739V     1.71V      788.4mV
7.42ns    1.478V     1.702V     320.6mV
10.54ns   615.9mV    1.508V     214mV
11.86ns   410.6mV    1.36V      201mV
18.64ns   249.8mV    508.5mV    179.1mV
29.98ns   217.9mV    323.9mV    174.3mV
225.6ns   211.3mV    279mV      173.9mV
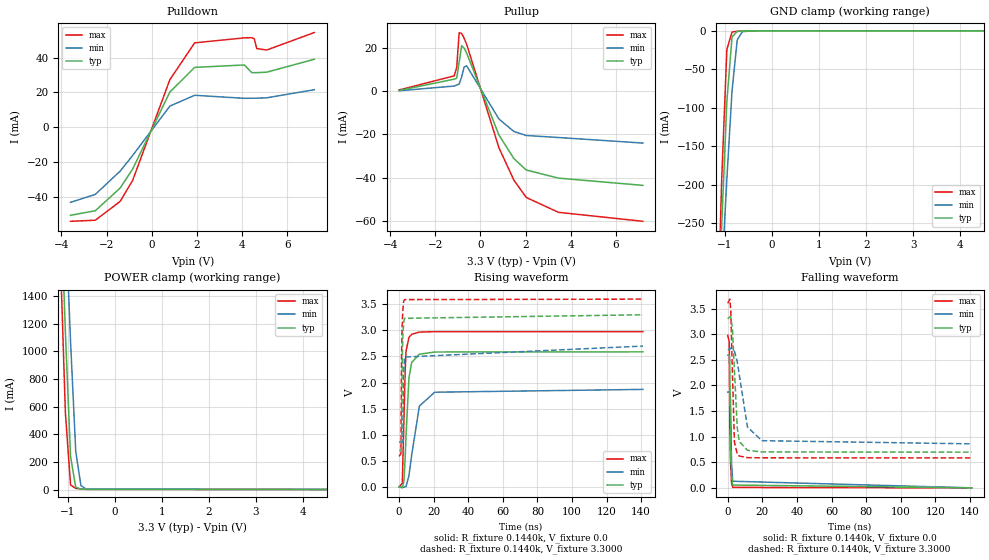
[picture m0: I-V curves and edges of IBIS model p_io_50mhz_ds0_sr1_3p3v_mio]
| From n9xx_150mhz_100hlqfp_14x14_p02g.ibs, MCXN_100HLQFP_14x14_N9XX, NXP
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[Model] p_io_50mhz_ds0_sr1_3p3v_mio
|   Model p_io_50mhz_ds0_sr1_3p3v_mio
| This model was characterised for following simulation conditions:
| External (pad) voltage:
|   - Typ: 3.3V,   - Min: 2.7V,   - Max: 3.6V
| Library cells for typ/min/max conditions are connected as defined below:
|  pad - External Pad
|  ipp_do_lv - Core Input
|  ipp_obe_lv - Output Buffer Enable
|  IOGC - NC
|  REFH3V3 - REFH3V3
|  REFL3V3 - REFL3V3
|  ZI - NC
|  abut_ncal_vddio[1] - vddio
|  abut_ncal_vddio[2] - vddio
|  abut_ncal_vddio[3] - vssio
|  abut_ncal_vddio[4] - vddio
|  abut_ncal_vddio[5] - vddio
|  abut_ncal_vddio[6] - vssio
|  abut_pcal_vddio[1] - vssio
|  abut_pcal_vddio[2] - vssio
|  abut_pcal_vddio[3] - vddio
|  abut_pcal_vddio[4] - vssio
|  abut_pcal_vddio[5] - vssio
|  abut_pcal_vddio[6] - vddio
|  ipp_do_1p8v - ipp_do_1p8v
|  ipp_dse_lv - 0
|  ipp_eftd_lv - NC
|  ipp_ina_mux_vddio - NC
|  ipp_ina_mux_vddio[0] - NC
|  ipp_ina_mux_vddio[1] - NC
|  ipp_ina_r0_vddio - NC
|  ipp_ina_r0a_vddio - NC
|  ipp_ina_r0b_vddio - NC
|  ipp_ina_r0c_vddio - NC
|  ipp_ina_r0d_vddio - NC
|  ipp_ina_r0e_vddio - NC
|  ipp_ina_r0f_vddio - NC
|  ipp_ina_r300_vddio - NC
|  ipp_ina_r300a_vddio - NC
|  ipp_ina_r300b_vddio - NC
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Model_type I/O
Polarity   Non-Inverting
Enable   Active-High
Vinl =   0.9900V
Vinh =   2.3100V
Vmeas =  1.6500V
Cref =   30.0000pF
Rref =   1.0000M
Vref =   3.3000V
C_comp   1.4363pF   1.3758pF   1.5227pF
|C_comp_pullup   0.7200pF   0.7523pF   0.6980pF
|C_comp_pulldown   0.6275pF   0.6820pF   0.5878pF
[Model Spec]
| variable   typ   min   max
Vinh   2.3100V   1.8900V   2.5200V
Vinl   0.9900V   0.8100V   1.0800V
[Temperature Range]   25.0000   0.1250k   -40.0000
[Voltage Range]   3.3000V   2.7000V   3.6000V
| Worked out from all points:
|   slope of the pulldown table from 0 to 0.495 V, typ, clamps not added: 36.8 ohm
|   slope of the pullup table from 0 to 0.495 V, typ, clamps not added: 37.8 ohm
|   GND clamp passes 1 mA (typ) near -0.74 V on its own axis
|   POWER clamp passes 1 mA (typ) near -0.54 V on its own axis
|   rising waveform, R_fixture 0.1440k, V_fixture 0.0: 20-80 % time 2.21ns typ, 4.84ns min, 1.35ns max; typ from 0 V to 2.59 V
|   rising waveform, R_fixture 0.1440k, V_fixture 3.3000: 20-80 % time 520ps typ, 547ps min, 514ps max; typ from 0.697 V to 3.3 V
|   falling waveform, R_fixture 0.1440k, V_fixture 0.0: 20-80 % time 562ps typ, 593ps min, 547ps max; typ from 2.59 V to 0 V
|   falling waveform, R_fixture 0.1440k, V_fixture 3.3000: 20-80 % time 2.17ns typ, 4.92ns min, 1.32ns max; typ from 3.3 V to 0.697 V
[Pulldown]
|Voltage   I(typ)   I(min)   I(max)
-3.6V     -50.71mA   -43.27mA   -54.18mA
-2.5V     -48.1mA    -38.69mA   -53.56mA
-1.4V     -35.02mA   -25.26mA   -42.7mA
-850mV    -24.18mA   -16.32mA   -30.7mA
800mV     20.23mA    12.14mA    27.32mA
1.9V      34.45mA    18.38mA    48.57mA
4.1V      35.83mA    16.63mA    51.44mA
4.43V     31.42mA    16.66mA    51.52mA
4.54V     31.41mA    16.69mA    50.94mA
4.65V     31.42mA    16.71mA    45.28mA
5.09V     31.67mA    16.92mA    44.44mA
7.2V      39.12mA    21.58mA    54.49mA
[Pullup]
|Voltage   I(typ)   I(min)   I(max)
-3.6V     390.2uA    234.7uA    600.5uA
-1.16V    5.607mA    2.418mA    7.152mA
-1.05V    6.059mA    2.87mA     11.01mA
-940mV    13.57mA    3.339mA    27.22mA
-830mV    21.13mA    6.682mA    26.77mA
-720mV    20.02mA    11.25mA    24.57mA
-610mV    17.72mA    11.8mA     21.82mA
820mV     -20.27mA   -12.85mA   -26.19mA
1.48V     -31.2mA    -18.62mA   -41.17mA
2.03V     -36.53mA   -20.52mA   -49.25mA
3.46V     -40.29mA   -21.45mA   -56.15mA
7.2V      -43.65mA   -24.03mA   -60.31mA
[GND_clamp]
|Voltage   I(typ)   I(min)   I(max)
-3.6V     -4.967A    -3.834A    -6.451A
-1.18V    -432.4mA   -454.2mA   -428.7mA
-1.07V    -252.8mA   -319.9mA   -193.4mA
-960mV    -91.54mA   -192mA     -24.27mA
-850mV    -8.013mA   -77.88mA   -1.462mA
-740mV    -731.9uA   -11.92mA   -724.8uA
-630mV    -284.5uA   -927.4uA   -315.1uA
-300mV    -508.9nA   -3.017uA   -108.6nA
7.2V      0A         0A         0A
[POWER_clamp]
|Voltage   I(typ)   I(min)   I(max)
-3.6V     26.34A     23.98A     28.82A
-1.16V    2.208A     2.937A     1.722A
-1.05V    1.14A      1.999A     556.4mA
-940mV    237.9mA    1.069A     33.46mA
-830mV    16.33mA    277.1mA    9.216mA
-720mV    4.663mA    29.2mA     4.86mA
-610mV    1.877mA    3.923mA    1.821mA
7.2V      0A         0A         0A
[Ramp]
| variable   typ   min   max
dV/dt_r  1.5537/2.2054n   1.1214/4.8410n   1.7857/1.3460n
dV/dt_f  1.5619/2.1733n   1.1045/4.9189n   1.8085/1.3236n
R_load = 0.1440k
[Rising Waveform]
R_fixture= 0.1440k
V_fixture= 0.0
V_fixture_min= 0.0
V_fixture_max= 0.0
|time   V(typ)   V(min)   V(max)
0s        4.584nV    239.2nV    15.27nV
1.827ns   -19.19mV   -4.531mV   67.88mV
2.782ns   111.9mV    -9.095mV   1.308V
3.473ns   558.1mV    2.983mV    2.208V
3.99ns    987.1mV    4.259mV    2.603V
5.674ns   2.092V     216.1mV    2.866V
7.227ns   2.383V     604.5mV    2.925V
11.7ns    2.544V     1.548V     2.968V
20.55ns   2.586V     1.815V     2.976V
141ns     2.589V     1.869V     2.976V
[Rising Waveform]
R_fixture= 0.1440k
V_fixture= 3.3000
V_fixture_min= 2.7000
V_fixture_max= 3.6000
|time   V(typ)   V(min)   V(max)
0s        696.8mV    859.1mV    585.8mV
1.048ns   697.2mV    859mV      638mV
1.344ns   743.6mV    859.5mV    2.268V
1.446ns   926.7mV    860.5mV    2.588V
1.692ns   2.144V     859.3mV    3.024V
1.915ns   2.646V     870.2mV    3.236V
2.173ns   2.915V     1.06V      3.398V
2.582ns   3.121V     2.121V     3.555V
3.081ns   3.232V     2.489V     3.591V
141ns     3.3V       2.7V       3.6V
[Falling Waveform]
R_fixture= 0.1440k
V_fixture= 0.0
V_fixture_min= 0.0
V_fixture_max= 0.0
|time   V(typ)   V(min)   V(max)
0s        2.589V     1.869V     2.976V
839.7ps   2.589V     1.869V     2.852V
924.4ps   2.571V     1.868V     2.619V
1.079ns   2.457V     1.87V      1.72V
1.195ns   2.183V     1.869V     1.262V
1.399ns   1.301V     1.833V     773.8mV
1.61ns    767.4mV    1.688V     488.4mV
2.201ns   233.7mV    481.9mV    89.28mV
2.877ns   54.8mV     129.2mV    8.987mV
141ns     1.784uV    4.055uV    1.178uV
[Falling Waveform]
R_fixture= 0.1440k
V_fixture= 3.3000
V_fixture_min= 2.7000
V_fixture_max= 3.6000
|time   V(typ)   V(min)   V(max)
0s        3.3V       2.7V       3.6V
1.175ns   3.337V     2.703V     3.684V
1.727ns   3.337V     2.728V     3.477V
2.7ns     3.102V     2.714V     2.231V
3.861ns   2.293V     2.67V      893.7mV
5.493ns   1.17V      2.461V     657.9mV
6.65ns    906.6mV    2.207V     621.5mV
11.4ns    733.2mV    1.187V     589.9mV
19.69ns   701.1mV    920.8mV    586.1mV
141ns     696.8mV    859.1mV    585.8mV
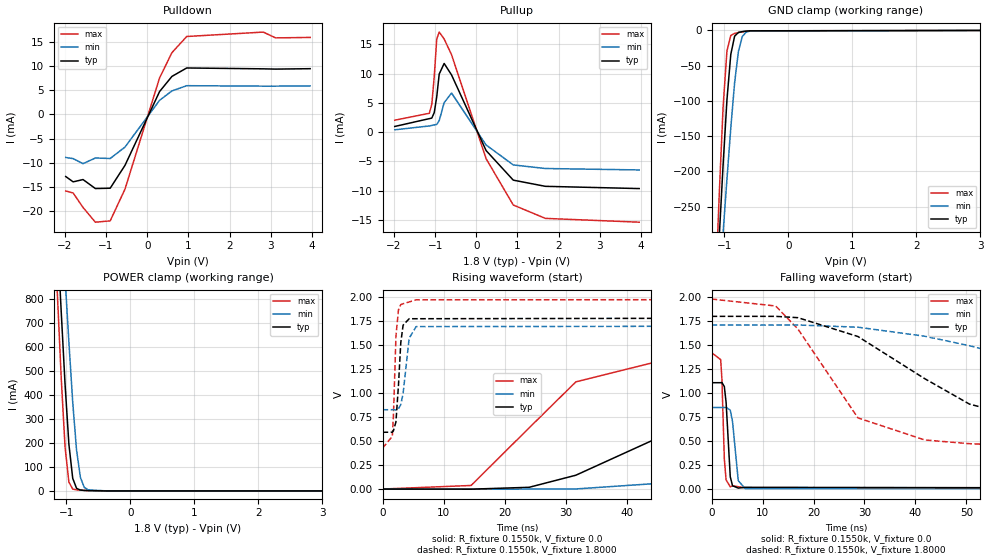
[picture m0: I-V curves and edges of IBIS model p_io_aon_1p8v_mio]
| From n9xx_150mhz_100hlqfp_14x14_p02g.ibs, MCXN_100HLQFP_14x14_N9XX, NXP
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[Model] p_io_aon_1p8v_mio
|   Model p_io_aon_1p8v_mio
| This model was characterised for following simulation conditions:
| External (pad) voltage:
|   - Typ: 1.8V,   - Min: 1.71V,   - Max: 1.98V
| Library cells for typ/min/max conditions are connected as defined below:
|  pad - External Pad
|  ipp_do_lv - Core Input
|  ipp_obe_lv - Output Buffer Enable
|  IOGC - NC
|  REFH3V3 - REFH3V3
|  REFL3V3 - REFL3V3
|  ZI - NC
|  abut_ncal_vddio[1] - vssio vddio vddio
|  abut_ncal_vddio[2] - vddio vddio vssio
|  abut_ncal_vddio[3] - vddio
|  abut_ncal_vddio[4] - vssio vddio vddio
|  abut_ncal_vddio[5] - vddio vddio vssio
|  abut_ncal_vddio[6] - vddio
|  abut_pcal_vddio[1] - vssio
|  abut_pcal_vddio[2] - vddio vssio vddio
|  abut_pcal_vddio[3] - vssio
|  abut_pcal_vddio[4] - vssio
|  abut_pcal_vddio[5] - vddio vssio vddio
|  abut_pcal_vddio[6] - vssio
|  ipp_do_1p8v - ipp_do_1p8v
|  ipp_eftd_lv - NC
|  ipp_ina_mux_vddio - NC
|  ipp_ina_mux_vddio[0] - NC
|  ipp_ina_mux_vddio[1] - NC
|  ipp_ina_r0_vddio - NC
|  ipp_ina_r0a_vddio - NC
|  ipp_ina_r0b_vddio - NC
|  ipp_ina_r0c_vddio - NC
|  ipp_ina_r0d_vddio - NC
|  ipp_ina_r0e_vddio - NC
|  ipp_ina_r0f_vddio - NC
|  ipp_ina_r300_vddio - NC
|  ipp_ina_r300a_vddio - NC
|  ipp_ina_r300b_vddio - NC
|  ipp_ina_r300c_vddio - NC
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Model_type I/O
Polarity   Non-Inverting
Enable   Active-High
Vinl =   0.5400V
Vinh =   1.2600V
Vmeas =  0.9000V
Cref =   30.0000pF
Rref =   1.0000M
Vref =   1.8000V
C_comp   1.3082pF   1.2616pF   1.4174pF
|C_comp_pullup   0.5655pF   0.5989pF   0.5405pF
|C_comp_pulldown   0.6521pF   0.7249pF   0.6270pF
[Model Spec]
| variable   typ   min   max
Vinh   1.2600V   1.1970V   1.3860V
Vinl   0.5400V   0.5130V   0.5940V
[Temperature Range]   25.0000   0.1250k   -40.0000
[Voltage Range]   1.8000V   1.7100V   1.9800V
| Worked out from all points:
|   slope of the pulldown table from 0 to 0.27 V, typ, clamps not added: 62.4 ohm
|   slope of the pullup table from 0 to 0.27 V, typ, clamps not added: 77.5 ohm
|   GND clamp passes 1 mA (typ) near -0.64 V on its own axis
|   POWER clamp passes 1 mA (typ) near -0.63 V on its own axis
|   rising waveform, R_fixture 0.1550k, V_fixture 0.0: 20-80 % time 25.4ns typ, 47.3ns min, 12.9ns max; typ from 0 V to 1.11 V
|   rising waveform, R_fixture 0.1550k, V_fixture 1.8000: 20-80 % time 632ps typ, 878ps min, 492ps max; typ from 0.592 V to 1.8 V
|   falling waveform, R_fixture 0.1550k, V_fixture 0.0: 20-80 % time 639ps typ, 845ps min, 495ps max; typ from 1.11 V to 0 V
|   falling waveform, R_fixture 0.1550k, V_fixture 1.8000: 20-80 % time 23.6ns typ, 45.1ns min, 11.9ns max; typ from 1.8 V to 0.592 V
[Pulldown]
|Voltage   I(typ)   I(min)   I(max)
-1.98V    -12.82mA   -8.883mA   -15.79mA
-1.8V     -13.92mA   -9.12mA    -16.22mA
-1.56V    -13.44mA   -10.16mA   -19.21mA
-1.26V    -15.3mA    -8.987mA   -22.25mA
-900mV    -15.23mA   -9.092mA   -21.98mA
-540mV    -10.5mA    -6.733mA   -15.41mA
300mV     4.734mA    2.929mA    7.544mA
600mV     7.861mA    4.866mA    12.77mA
960mV     9.608mA    5.948mA    16.11mA
2.82V     9.429mA    5.854mA    17.02mA
3.12V     9.374mA    5.855mA    15.82mA
3.96V     9.46mA     5.905mA    15.92mA
[Pullup]
|Voltage   I(typ)   I(min)   I(max)
-1.98V    970.1uA    399.7uA    2.041mA
-1.14V    2.306mA    1.059mA    3.217mA
-1.08V    2.399mA    1.145mA    4.761mA
-1.02V    3.355mA    1.234mA    9.541mA
-960mV    6.03mA     1.325mA    15.88mA
-900mV    9.91mA     1.972mA    17.07mA
-780mV    11.72mA    5.03mA     15.9mA
-600mV    9.761mA    6.668mA    13.21mA
240mV     -3.146mA   -2.19mA    -4.535mA
900mV     -8.187mA   -5.593mA   -12.43mA
1.68V     -9.242mA   -6.203mA   -14.71mA
3.96V     -9.624mA   -6.445mA   -15.36mA
[GND_clamp]
|Voltage   I(typ)   I(min)   I(max)
-1.98V    -2.029A    -1.716A    -2.516A
-1.14V    -399.2mA   -446.6mA   -369.9mA
-1.08V    -292.8mA   -366.2mA   -232.1mA
-1.02V    -191mA     -287.4mA   -109mA
-960mV    -98.91mA   -211.2mA   -29.36mA
-900mV    -34.26mA   -138.9mA   -7.283mA
-840mV    -8.248mA   -74.31mA   -4.319mA
-780mV    -2.995mA   -29.56mA   -3.112mA
-720mV    -1.791mA   -8.837mA   -2.149mA
-660mV    -1.158mA   -2.642mA   -1.361mA
-600mV    -697.2uA   -1.05mA    -760.6uA
3.96V     0A         0A         0A
[POWER_clamp]
|Voltage   I(typ)   I(min)   I(max)
-1.98V    5.575A     5.314A     6.031A
-1.14V    1.063A     1.433A     822.6mA
-1.08V    748.7mA    1.161A     472.7mA
-1.02V    446mA      889.8mA    183.6mA
-960mV    194.9mA    621.5mA    36.74mA
-900mV    52.34mA    369.1mA    7.81mA
-840mV    10.74mA    169.6mA    4.436mA
-780mV    3.619mA    56.13mA    3.182mA
-720mV    2.073mA    15.03mA    2.194mA
-660mV    1.305mA    4.298mA    1.374mA
-360mV    5.031uA    27.49uA    1.319uA
3.96V     0A         0A         0A
[Ramp]
| variable   typ   min   max
dV/dt_r  0.6653/25.3763n   0.5077/47.2667n   0.8533/12.9131n
dV/dt_f  0.7248/23.6164n   0.5271/45.0567n   0.9321/11.9085n
R_load = 0.1550k
[Rising Waveform]
R_fixture= 0.1550k
V_fixture= 0.0
V_fixture_min= 0.0
V_fixture_max= 0.0
|time   V(typ)   V(min)   V(max)
0s        394.1pV    138.2nV    9.262pV
14.47ns   -1.258mV   -1.189mV   37.3mV
23.97ns   18.27mV    -558.9uV   638mV
31.6ns    144.1mV    979.2uV    1.117V
45.76ns   554.7mV    62.23mV    1.342V
56.27ns   826.9mV    163.5mV    1.385V
66.74ns   956.7mV    291.2mV    1.404V
90.01ns   1.057V     573.9mV    1.418V
113ns     1.089V     718.5mV    1.421V
246.8ns   1.109V     846.2mV    1.422V
[Rising Waveform]
R_fixture= 0.1550k
V_fixture= 1.8000
V_fixture_min= 1.7100
V_fixture_max= 1.9800
|time   V(typ)   V(min)   V(max)
0s        591.7mV    826.7mV    426.4mV
1.595ns   592.6mV    826.8mV    549.4mV
1.771ns   605.8mV    826.7mV    748.2mV
2.189ns   699.7mV    824.3mV    1.592V
2.602ns   1.082V     836.6mV    1.867V
2.981ns   1.525V     879.9mV    1.923V
3.36ns    1.708V     995.8mV    1.931V
4.353ns   1.775V     1.572V     1.95V
5.494ns   1.775V     1.693V     1.972V
246.8ns   1.8V       1.71V      1.98V
[Falling Waveform]
R_fixture= 0.1550k
V_fixture= 0.0
V_fixture_min= 0.0
V_fixture_max= 0.0
|time   V(typ)   V(min)   V(max)
0s        1.109V     850.8mV    1.422V
1.789ns   1.109V     850.8mV    1.349V
2.027ns   1.111V     850.8mV    1.148V
2.503ns   1.069V     850.7mV    314.4mV
2.851ns   904.1mV    851.1mV    95.87mV
3.666ns   129.3mV    823.8mV    24.52mV
4.108ns   35.95mV    706.5mV    34.13mV
5.233ns   11.01mV    88.82mV    25.58mV
6.593ns   19.13mV    6.218mV    14.83mV
246.8ns   180nV      2.853uV    11.18nV
[Falling Waveform]
R_fixture= 0.1550k
V_fixture= 1.8000
V_fixture_min= 1.7100
V_fixture_max= 1.9800
|time   V(typ)   V(min)   V(max)
0s        1.8V       1.71V      1.98V
12.57ns   1.8V       1.709V     1.908V
16.95ns   1.786V     1.71V      1.667V
28.71ns   1.59V      1.687V     742.4mV
41.81ns   1.151V     1.593V     512.5mV
50.6ns    885.8mV    1.494V     473.7mV
59.76ns   759.2mV    1.369V     453.4mV
81.35ns   655.9mV    1.087V     434.5mV
103.8ns   619.4mV    955.8mV    428.8mV
246.8ns   591.9mV    831.6mV    426.4mV
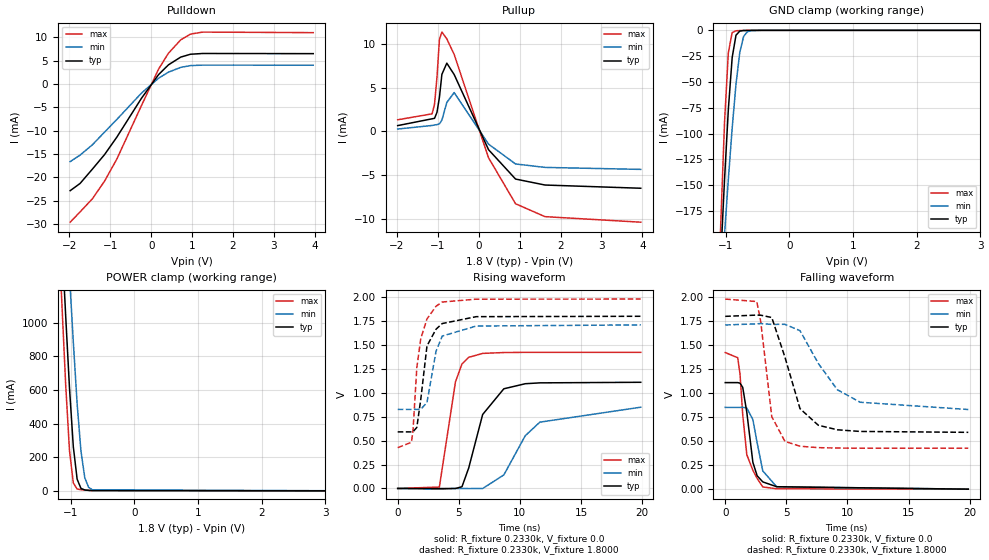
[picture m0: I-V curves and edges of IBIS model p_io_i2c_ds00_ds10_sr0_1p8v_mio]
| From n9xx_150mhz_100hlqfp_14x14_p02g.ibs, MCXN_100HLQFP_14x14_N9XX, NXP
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[Model] p_io_i2c_ds00_ds10_sr0_1p8v_mio
|   Model p_io_i2c_ds00_ds10_sr0_1p8v_mio
| This model was characterised for following simulation conditions:
| External (pad) voltage:
|   - Typ: 1.8V,   - Min: 1.71V,   - Max: 1.98V
| Library cells for typ/min/max conditions are connected as defined below:
|  pad - External Pad
|  ipp_do_lv - Core Input
|  ipp_obe_lv - Output Buffer Enable
|  IOGC - NC
|  REFH3V3 - REFH3V3
|  REFL3V3 - REFL3V3
|  ZI - NC
|  abut_ncal_vddio[1] - vssio vddio vddio
|  abut_ncal_vddio[2] - vddio vddio vssio
|  abut_ncal_vddio[3] - vddio
|  abut_ncal_vddio[4] - vssio vddio vddio
|  abut_ncal_vddio[5] - vddio vddio vssio
|  abut_ncal_vddio[6] - vddio
|  abut_pcal_vddio[1] - vssio
|  abut_pcal_vddio[2] - vddio vssio vddio
|  abut_pcal_vddio[3] - vssio
|  abut_pcal_vddio[4] - vssio
|  abut_pcal_vddio[5] - vddio vssio vddio
|  abut_pcal_vddio[6] - vssio
|  ipp_do_1p8v - ipp_do_1p8v
|  ipp_dse_lv[0] - 0
|  ipp_dse_lv[1] - 0
|  ipp_eftd_lv - NC
|  ipp_ina_mux_vddio - NC
|  ipp_ina_mux_vddio[0] - NC
|  ipp_ina_mux_vddio[1] - NC
|  ipp_ina_r0_vddio - NC
|  ipp_ina_r0a_vddio - NC
|  ipp_ina_r0b_vddio - NC
|  ipp_ina_r0c_vddio - NC
|  ipp_ina_r0d_vddio - NC
|  ipp_ina_r0e_vddio - NC
|  ipp_ina_r0f_vddio - NC
|  ipp_ina_r300_vddio - NC
|  ipp_ina_r300a_vddio - NC
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Model_type I/O
Polarity   Non-Inverting
Enable   Active-High
Vinl =   0.5400V
Vinh =   1.2600V
Vmeas =  0.9000V
Cref =   30.0000pF
Rref =   1.0000M
Vref =   1.8000V
C_comp   1.4328pF   1.3910pF   1.4871pF
|C_comp_pullup   0.6295pF   0.6727pF   0.5893pF
|C_comp_pulldown   0.7021pF   0.7083pF   0.7045pF
[Model Spec]
| variable   typ   min   max
Vinh   1.2600V   1.1970V   1.3860V
Vinl   0.5400V   0.5130V   0.5940V
[Temperature Range]   25.0000   0.1250k   -40.0000
[Voltage Range]   1.8000V   1.7100V   1.9800V
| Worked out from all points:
|   slope of the pulldown table from 0 to 0.27 V, typ, clamps not added: 93.8 ohm
|   slope of the pullup table from 0 to 0.27 V, typ, clamps not added: 116 ohm
|   GND clamp passes 1 mA (typ) near -0.78 V on its own axis
|   POWER clamp passes 1 mA (typ) near -0.58 V on its own axis
|   rising waveform, R_fixture 0.2330k, V_fixture 0.0: 20-80 % time 1.68ns typ, 2.63ns min, 970ps max; typ from 0 V to 1.11 V
|   rising waveform, R_fixture 0.2330k, V_fixture 1.8000: 20-80 % time 732ps typ, 763ps min, 788ps max; typ from 0.592 V to 1.8 V
|   falling waveform, R_fixture 0.2330k, V_fixture 0.0: 20-80 % time 685ps typ, 785ps min, 649ps max; typ from 1.11 V to 0 V
|   falling waveform, R_fixture 0.2330k, V_fixture 1.8000: 20-80 % time 1.59ns typ, 2.73ns min, 862ps max; typ from 1.8 V to 0.592 V
[Pulldown]
|Voltage   I(typ)   I(min)   I(max)
-1.98V    -22.85mA   -16.63mA   -29.61mA
-1.74V    -21.32mA   -15.24mA   -27.42mA
-1.44V    -18.26mA   -13.04mA   -24.62mA
-1.14V    -15.12mA   -10.3mA    -20.81mA
-840mV    -11.38mA   -7.585mA   -16.08mA
-240mV    -3.077mA   -1.958mA   -4.652mA
180mV     2.022mA    1.25mA     3.2mA
420mV     4.109mA    2.543mA    6.592mA
720mV     5.775mA    3.575mA    9.468mA
960mV     6.391mA    3.957mA    10.71mA
1.26V     6.554mA    4.059mA    11.14mA
3.96V     6.52mA     4.05mA     11.02mA
[Pullup]
|Voltage   I(typ)   I(min)   I(max)
-1.98V    661.3uA    267.4uA    1.327mA
-1.14V    1.439mA    676.4uA    2.008mA
-1.08V    1.492mA    726.2uA    3.099mA
-1.02V    2.182mA    777.6uA    6.192mA
-960mV    3.913mA    861.9uA    10.52mA
-900mV    6.522mA    1.286mA    11.36mA
-780mV    7.802mA    3.306mA    10.59mA
-600mV    6.502mA    4.441mA    8.8mA
240mV     -2.096mA   -1.459mA   -3.021mA
900mV     -5.454mA   -3.727mA   -8.28mA
1.62V     -6.138mA   -4.122mA   -9.756mA
3.96V     -6.506mA   -4.349mA   -10.39mA
[GND_clamp]
|Voltage   I(typ)   I(min)   I(max)
-1.98V    -1.586A    -1.229A    -2.1A
-1.08V    -221.4mA   -253.6mA   -188.5mA
-1.02V    -144.6mA   -197.7mA   -89.32mA
-960mV    -76.59mA   -144.3mA   -21.58mA
-900mV    -26.43mA   -94.89mA   -2.183mA
-840mV    -4.754mA   -52.29mA   -428.7uA
-780mV    -708.9uA   -21.31mA   -240uA
-720mV    -194.5uA   -5.864mA   -159.9uA
-660mV    -97.62uA   -1.274mA   -100.6uA
-600mV    -55.49uA   -286.4uA   -56.47uA
-420mV    -4.265uA   -10.7uA    -2.74uA
3.96V     0A         0A         0A
[POWER_clamp]
|Voltage   I(typ)   I(min)   I(max)
-1.98V    7.929A     7.752A     8.366A
-1.2V     1.949A     2.483A     1.628A
-1.14V    1.495A     2.081A     1.12A
-1.08V    1.044A     1.68A      633.7mA
-1.02V    613.2mA    1.282A     240.4mA
-960mV    264mA      886.2mA    47.43mA
-900mV    69.94mA    519.6mA    11.58mA
-840mV    15.1mA     237.3mA    7.049mA
-780mV    5.589mA    78.54mA    5.099mA
-720mV    3.316mA    21.56mA    3.521mA
-660mV    2.102mA    6.487mA    2.205mA
3.96V     0A         0A         0A
[Ramp]
| variable   typ   min   max
dV/dt_r  0.6658/1.6752n   0.5097/2.6271n   0.8537/0.9703n
dV/dt_f  0.7248/1.5864n   0.5282/2.7284n   0.9322/0.8624n
R_load = 0.2330k
[Rising Waveform]
R_fixture= 0.2330k
V_fixture= 0.0
V_fixture_min= 0.0
V_fixture_max= 0.0
|time   V(typ)   V(min)   V(max)
0s        729.6pV    308.8nV    24.89pV
3.41ns    -1.041mV   -7.331mV   14.8mV
4.728ns   -336.2uV   284.9uV    1.115V
5.26ns    18.28mV    -459.6uV   1.302V
5.81ns    213.8mV    -1.214mV   1.371V
6.952ns   773.4mV    -534.3uV   1.412V
8.684ns   1.042V     141.7mV    1.421V
10.44ns   1.095V     551.4mV    1.423V
11.63ns   1.104V     693.2mV    1.423V
19.89ns   1.11V      849.5mV    1.423V
[Rising Waveform]
R_fixture= 0.2330k
V_fixture= 1.8000
V_fixture_min= 1.7100
V_fixture_max= 1.9800
|time   V(typ)   V(min)   V(max)
0s        591.6mV    826.6mV    426.4mV
1.125ns   591.4mV    826.6mV    482.8mV
1.254ns   592.6mV    826.6mV    608.1mV
1.565ns   638.5mV    826.6mV    1.264V
1.887ns   930.6mV    828.2mV    1.566V
2.395ns   1.49V      897.4mV    1.772V
3.137ns   1.665V     1.435V     1.905V
3.642ns   1.724V     1.593V     1.949V
6.423ns   1.796V     1.698V     1.979V
19.89ns   1.8V       1.71V      1.98V
[Falling Waveform]
R_fixture= 0.2330k
V_fixture= 0.0
V_fixture_min= 0.0
V_fixture_max= 0.0
|time   V(typ)   V(min)   V(max)
0s        1.11V      851.7mV    1.423V
1.023ns   1.11V      851.5mV    1.369V
1.211ns   1.104V     851.6mV    1.198V
1.433ns   1.06V      852.5mV    774.9mV
1.767ns   799.9mV    845.3mV    358.3mV
2.264ns   279mV      723.9mV    197.1mV
2.614ns   139.2mV    481.5mV    111.4mV
3.075ns   75.6mV     189.9mV    22.96mV
4.211ns   25.45mV    24.8mV     4.081mV
19.89ns   4.845uV    46.46uV    409.4nV
[Falling Waveform]
R_fixture= 0.2330k
V_fixture= 1.8000
V_fixture_min= 1.7100
V_fixture_max= 1.9800
|time   V(typ)   V(min)   V(max)
0s        1.8V       1.71V      1.98V
2.582ns   1.813V     1.722V     1.954V
2.902ns   1.812V     1.725V     1.748V
3.809ns   1.788V     1.716V     755.2mV
4.884ns   1.376V     1.717V     498mV
6.119ns   838.8mV    1.651V     446.9mV
7.616ns   665.7mV    1.31V      432.4mV
9.172ns   618.5mV    1.036V     428.1mV
11.04ns   601.2mV    905.4mV    426.9mV
19.89ns   591.9mV    829.7mV    426.4mV
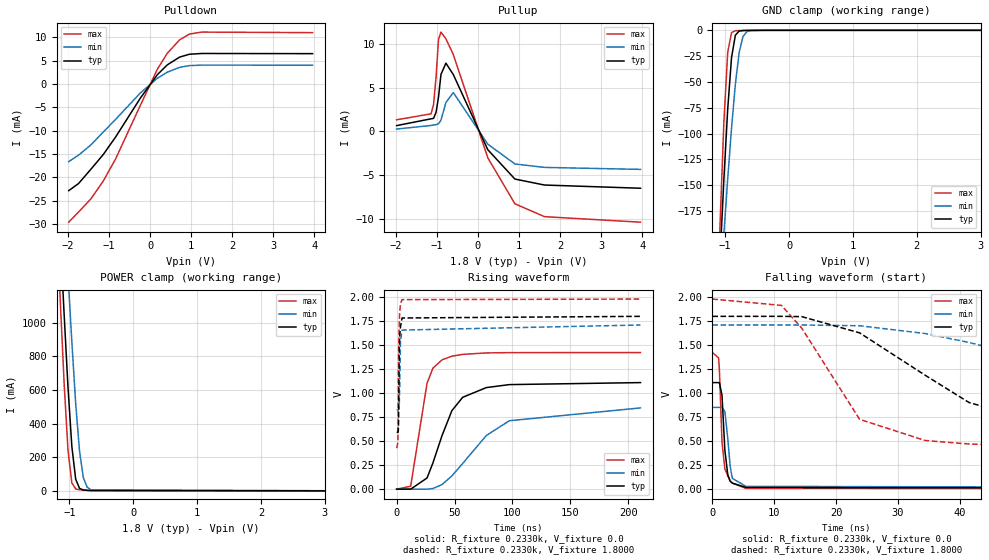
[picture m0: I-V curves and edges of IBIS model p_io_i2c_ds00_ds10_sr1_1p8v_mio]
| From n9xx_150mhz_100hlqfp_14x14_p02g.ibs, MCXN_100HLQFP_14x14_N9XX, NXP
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[Model] p_io_i2c_ds00_ds10_sr1_1p8v_mio
|   Model p_io_i2c_ds00_ds10_sr1_1p8v_mio
| This model was characterised for following simulation conditions:
| External (pad) voltage:
|   - Typ: 1.8V,   - Min: 1.71V,   - Max: 1.98V
| Library cells for typ/min/max conditions are connected as defined below:
|  pad - External Pad
|  ipp_do_lv - Core Input
|  ipp_obe_lv - Output Buffer Enable
|  IOGC - NC
|  REFH3V3 - REFH3V3
|  REFL3V3 - REFL3V3
|  ZI - NC
|  abut_ncal_vddio[1] - vssio vddio vddio
|  abut_ncal_vddio[2] - vddio vddio vssio
|  abut_ncal_vddio[3] - vddio
|  abut_ncal_vddio[4] - vssio vddio vddio
|  abut_ncal_vddio[5] - vddio vddio vssio
|  abut_ncal_vddio[6] - vddio
|  abut_pcal_vddio[1] - vssio
|  abut_pcal_vddio[2] - vddio vssio vddio
|  abut_pcal_vddio[3] - vssio
|  abut_pcal_vddio[4] - vssio
|  abut_pcal_vddio[5] - vddio vssio vddio
|  abut_pcal_vddio[6] - vssio
|  ipp_do_1p8v - ipp_do_1p8v
|  ipp_dse_lv[0] - 0
|  ipp_dse_lv[1] - 0
|  ipp_eftd_lv - NC
|  ipp_ina_mux_vddio - NC
|  ipp_ina_mux_vddio[0] - NC
|  ipp_ina_mux_vddio[1] - NC
|  ipp_ina_r0_vddio - NC
|  ipp_ina_r0a_vddio - NC
|  ipp_ina_r0b_vddio - NC
|  ipp_ina_r0c_vddio - NC
|  ipp_ina_r0d_vddio - NC
|  ipp_ina_r0e_vddio - NC
|  ipp_ina_r0f_vddio - NC
|  ipp_ina_r300_vddio - NC
|  ipp_ina_r300a_vddio - NC
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Model_type I/O
Polarity   Non-Inverting
Enable   Active-High
Vinl =   0.5400V
Vinh =   1.2600V
Vmeas =  0.9000V
Cref =   30.0000pF
Rref =   1.0000M
Vref =   1.8000V
C_comp   1.4328pF   1.3910pF   1.4871pF
|C_comp_pullup   0.6299pF   0.6731pF   0.5896pF
|C_comp_pulldown   0.7018pF   0.7079pF   0.7042pF
[Model Spec]
| variable   typ   min   max
Vinh   1.2600V   1.1970V   1.3860V
Vinl   0.5400V   0.5130V   0.5940V
[Temperature Range]   25.0000   0.1250k   -40.0000
[Voltage Range]   1.8000V   1.7100V   1.9800V
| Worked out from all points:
|   slope of the pulldown table from 0 to 0.27 V, typ, clamps not added: 93.8 ohm
|   slope of the pullup table from 0 to 0.27 V, typ, clamps not added: 116 ohm
|   GND clamp passes 1 mA (typ) near -0.78 V on its own axis
|   POWER clamp passes 1 mA (typ) near -0.58 V on its own axis
|   rising waveform, R_fixture 0.2330k, V_fixture 0.0: 20-80 % time 21.6ns typ, 40.7ns min, 10.8ns max; typ from 0 V to 1.11 V
|   rising waveform, R_fixture 0.2330k, V_fixture 1.8000: 20-80 % time 722ps typ, 757ps min, 789ps max; typ from 0.592 V to 1.8 V
|   falling waveform, R_fixture 0.2330k, V_fixture 0.0: 20-80 % time 648ps typ, 728ps min, 623ps max; typ from 1.11 V to 0 V
|   falling waveform, R_fixture 0.2330k, V_fixture 1.8000: 20-80 % time 18.5ns typ, 36.2ns min, 9.12ns max; typ from 1.8 V to 0.592 V
[Pulldown]
|Voltage   I(typ)   I(min)   I(max)
-1.98V    -22.85mA   -16.63mA   -29.61mA
-1.74V    -21.32mA   -15.24mA   -27.42mA
-1.44V    -18.26mA   -13.04mA   -24.62mA
-1.14V    -15.12mA   -10.3mA    -20.81mA
-840mV    -11.38mA   -7.585mA   -16.08mA
-240mV    -3.077mA   -1.958mA   -4.652mA
180mV     2.022mA    1.25mA     3.2mA
420mV     4.109mA    2.543mA    6.592mA
720mV     5.775mA    3.575mA    9.468mA
960mV     6.391mA    3.957mA    10.71mA
1.26V     6.554mA    4.059mA    11.14mA
3.96V     6.52mA     4.05mA     11.02mA
[Pullup]
|Voltage   I(typ)   I(min)   I(max)
-1.98V    661.3uA    267.4uA    1.327mA
-1.14V    1.439mA    676.4uA    2.008mA
-1.08V    1.492mA    726.2uA    3.099mA
-1.02V    2.182mA    777.6uA    6.192mA
-960mV    3.913mA    861.9uA    10.52mA
-900mV    6.522mA    1.286mA    11.36mA
-780mV    7.802mA    3.306mA    10.59mA
-600mV    6.502mA    4.441mA    8.8mA
240mV     -2.096mA   -1.459mA   -3.021mA
900mV     -5.454mA   -3.727mA   -8.28mA
1.62V     -6.138mA   -4.122mA   -9.756mA
3.96V     -6.506mA   -4.348mA   -10.39mA
[GND_clamp]
|Voltage   I(typ)   I(min)   I(max)
-1.98V    -1.586A    -1.229A    -2.1A
-1.08V    -221.4mA   -253.6mA   -188.5mA
-1.02V    -144.6mA   -197.7mA   -89.32mA
-960mV    -76.59mA   -144.3mA   -21.58mA
-900mV    -26.43mA   -94.89mA   -2.183mA
-840mV    -4.754mA   -52.29mA   -428.7uA
-780mV    -708.9uA   -21.31mA   -240uA
-720mV    -194.5uA   -5.864mA   -159.9uA
-660mV    -97.62uA   -1.274mA   -100.6uA
-600mV    -55.49uA   -286.4uA   -56.47uA
-420mV    -4.265uA   -10.7uA    -2.74uA
3.96V     0A         0A         0A
[POWER_clamp]
|Voltage   I(typ)   I(min)   I(max)
-1.98V    7.929A     7.752A     8.366A
-1.2V     1.949A     2.483A     1.628A
-1.14V    1.495A     2.081A     1.12A
-1.08V    1.044A     1.68A      633.7mA
-1.02V    613.2mA    1.282A     240.4mA
-960mV    264mA      886.2mA    47.43mA
-900mV    69.94mA    519.6mA    11.58mA
-840mV    15.1mA     237.3mA    7.049mA
-780mV    5.589mA    78.54mA    5.099mA
-720mV    3.316mA    21.56mA    3.521mA
-660mV    2.102mA    6.487mA    2.205mA
3.96V     0A         0A         0A
[Ramp]
| variable   typ   min   max
dV/dt_r  0.6658/21.5740n   0.5078/40.7080n   0.8537/10.8086n
dV/dt_f  0.7250/18.5324n   0.5277/36.2016n   0.9322/9.1163n
R_load = 0.2330k
[Rising Waveform]
R_fixture= 0.2330k
V_fixture= 0.0
V_fixture_min= 0.0
V_fixture_max= 0.0
|time   V(typ)   V(min)   V(max)
0s        729.6pV    308.8nV    24.89pV
12.12ns   -47.87uV   -21.69uV   30.53mV
26.26ns   116.6mV    201.7uV    1.104V
31.37ns   274.2mV    6.492mV    1.261V
39.25ns   559.4mV    48.4mV     1.347V
47.72ns   817.9mV    137.9mV    1.385V
57.02ns   956.7mV    267.9mV    1.404V
77.46ns   1.058V     558.9mV    1.419V
97.29ns   1.089V     712.6mV    1.422V
210.6ns   1.11V      846.3mV    1.423V
[Rising Waveform]
R_fixture= 0.2330k
V_fixture= 1.8000
V_fixture_min= 1.7100
V_fixture_max= 1.9800
|time   V(typ)   V(min)   V(max)
0s        591.6mV    826.6mV    426.4mV
1.109ns   591.4mV    826.6mV    487.5mV
1.224ns   591.8mV    826.6mV    602.7mV
1.436ns   610.3mV    826.6mV    1.116V
1.648ns   690.4mV    826.4mV    1.399V
2.267ns   1.435V     871.2mV    1.739V
2.626ns   1.591V     1.063V     1.837V
3.322ns   1.692V     1.538V     1.933V
4.697ns   1.783V     1.657V     1.974V
210.6ns   1.8V       1.71V      1.98V
[Falling Waveform]
R_fixture= 0.2330k
V_fixture= 0.0
V_fixture_min= 0.0
V_fixture_max= 0.0
|time   V(typ)   V(min)   V(max)
0s        1.11V      851.7mV    1.423V
1.012ns   1.11V      851.5mV    1.367V
1.143ns   1.108V     851.5mV    1.237V
1.556ns   978.4mV    852.6mV    489.3mV
2.019ns   406.2mV    807.6mV    212.3mV
2.491ns   150.2mV    527.7mV    139.1mV
2.865ns   82.99mV    243.7mV    90.96mV
3.218ns   63.79mV    112.9mV    62.3mV
5.417ns   18.05mV    29.13mV    8.448mV
210.6ns   223nV      2.842uV    54.07nV
[Falling Waveform]
R_fixture= 0.2330k
V_fixture= 1.8000
V_fixture_min= 1.7100
V_fixture_max= 1.9800
|time   V(typ)   V(min)   V(max)
0s        1.8V       1.71V      1.98V
11.17ns   1.8V       1.71V      1.914V
14.44ns   1.797V     1.71V      1.677V
23.79ns   1.628V     1.702V     727.4mV
34.39ns   1.186V     1.621V     506.5mV
41.46ns   902.6mV    1.528V     470.5mV
49.24ns   759mV      1.4V       450.9mV
68.66ns   649mV      1.083V     432.9mV
86.9ns    616.5mV    953.1mV    428.4mV
210.6ns   591.7mV    830.5mV    426.4mV
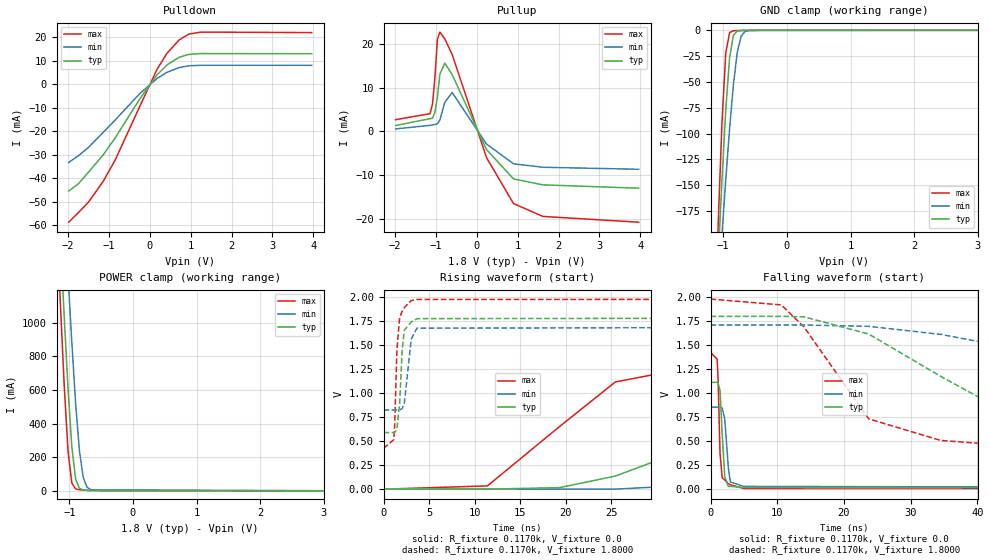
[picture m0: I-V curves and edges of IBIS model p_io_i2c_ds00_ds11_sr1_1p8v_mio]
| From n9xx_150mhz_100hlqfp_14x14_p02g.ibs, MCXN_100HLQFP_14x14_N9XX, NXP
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[Model] p_io_i2c_ds00_ds11_sr1_1p8v_mio
|   Model p_io_i2c_ds00_ds11_sr1_1p8v_mio
| This model was characterised for following simulation conditions:
| External (pad) voltage:
|   - Typ: 1.8V,   - Min: 1.71V,   - Max: 1.98V
| Library cells for typ/min/max conditions are connected as defined below:
|  pad - External Pad
|  ipp_do_lv - Core Input
|  ipp_obe_lv - Output Buffer Enable
|  IOGC - NC
|  REFH3V3 - REFH3V3
|  REFL3V3 - REFL3V3
|  ZI - NC
|  abut_ncal_vddio[1] - vssio vddio vddio
|  abut_ncal_vddio[2] - vddio vddio vssio
|  abut_ncal_vddio[3] - vddio
|  abut_ncal_vddio[4] - vssio vddio vddio
|  abut_ncal_vddio[5] - vddio vddio vssio
|  abut_ncal_vddio[6] - vddio
|  abut_pcal_vddio[1] - vssio
|  abut_pcal_vddio[2] - vddio vssio vddio
|  abut_pcal_vddio[3] - vssio
|  abut_pcal_vddio[4] - vssio
|  abut_pcal_vddio[5] - vddio vssio vddio
|  abut_pcal_vddio[6] - vssio
|  ipp_do_1p8v - ipp_do_1p8v
|  ipp_dse_lv[0] - 0
|  ipp_dse_lv[1] - vdd_lv
|  ipp_eftd_lv - NC
|  ipp_ina_mux_vddio - NC
|  ipp_ina_mux_vddio[0] - NC
|  ipp_ina_mux_vddio[1] - NC
|  ipp_ina_r0_vddio - NC
|  ipp_ina_r0a_vddio - NC
|  ipp_ina_r0b_vddio - NC
|  ipp_ina_r0c_vddio - NC
|  ipp_ina_r0d_vddio - NC
|  ipp_ina_r0e_vddio - NC
|  ipp_ina_r0f_vddio - NC
|  ipp_ina_r300_vddio - NC
|  ipp_ina_r300a_vddio - NC
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Model_type I/O
Polarity   Non-Inverting
Enable   Active-High
Vinl =   0.5400V
Vinh =   1.2600V
Vmeas =  0.9000V
Cref =   30.0000pF
Rref =   1.0000M
Vref =   1.8000V
C_comp   1.4328pF   1.3910pF   1.4871pF
|C_comp_pullup   0.6298pF   0.6730pF   0.5895pF
|C_comp_pulldown   0.7019pF   0.7080pF   0.7043pF
[Model Spec]
| variable   typ   min   max
Vinh   1.2600V   1.1970V   1.3860V
Vinl   0.5400V   0.5130V   0.5940V
[Temperature Range]   25.0000   0.1250k   -40.0000
[Voltage Range]   1.8000V   1.7100V   1.9800V
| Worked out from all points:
|   slope of the pulldown table from 0 to 0.27 V, typ, clamps not added: 46.9 ohm
|   slope of the pullup table from 0 to 0.27 V, typ, clamps not added: 58.1 ohm
|   GND clamp passes 1 mA (typ) near -0.78 V on its own axis
|   POWER clamp passes 1 mA (typ) near -0.58 V on its own axis
|   rising waveform, R_fixture 0.1170k, V_fixture 0.0: 20-80 % time 21ns typ, 39.5ns min, 10.6ns max; typ from 0 V to 1.11 V
|   rising waveform, R_fixture 0.1170k, V_fixture 1.8000: 20-80 % time 403ps typ, 512ps min, 360ps max; typ from 0.59 V to 1.8 V
|   falling waveform, R_fixture 0.1170k, V_fixture 0.0: 20-80 % time 424ps typ, 544ps min, 355ps max; typ from 1.11 V to 0 V
|   falling waveform, R_fixture 0.1170k, V_fixture 1.8000: 20-80 % time 19ns typ, 37ns min, 9.42ns max; typ from 1.8 V to 0.59 V
[Pulldown]
|Voltage   I(typ)   I(min)   I(max)
-1.98V    -45.46mA   -33.22mA   -58.7mA
-1.74V    -42.29mA   -30.37mA   -54.56mA
-1.5V     -37.5mA    -26.94mA   -50.24mA
-1.14V    -30.1mA    -20.51mA   -41.41mA
-840mV    -22.72mA   -15.13mA   -32.11mA
-240mV    -6.149mA   -3.914mA   -9.292mA
180mV     4.04mA     2.499mA    6.393mA
420mV     8.21mA     5.083mA    13.17mA
720mV     11.54mA    7.144mA    18.92mA
960mV     12.77mA    7.907mA    21.41mA
1.26V     13.1mA     8.11mA     22.25mA
3.96V     13.03mA    8.088mA    22.03mA
[Pullup]
|Voltage   I(typ)   I(min)   I(max)
-1.98V    1.322mA    535uA      2.661mA
-1.14V    2.892mA    1.357mA    4.033mA
-1.08V    2.998mA    1.458mA    6.209mA
-1.02V    4.373mA    1.562mA    12.42mA
-960mV    7.844mA    1.723mA    21.06mA
-900mV    13.06mA    2.576mA    22.72mA
-780mV    15.6mA     6.622mA    21.17mA
-600mV    13mA       8.883mA    17.6mA
240mV     -4.193mA   -2.918mA   -6.042mA
900mV     -10.91mA   -7.454mA   -16.56mA
1.62V     -12.28mA   -8.245mA   -19.51mA
3.96V     -13.04mA   -8.709mA   -20.83mA
[GND_clamp]
|Voltage   I(typ)   I(min)   I(max)
-1.98V    -1.586A    -1.229A    -2.1A
-1.08V    -221.4mA   -253.6mA   -188.5mA
-1.02V    -144.6mA   -197.7mA   -89.32mA
-960mV    -76.59mA   -144.3mA   -21.58mA
-900mV    -26.43mA   -94.89mA   -2.183mA
-840mV    -4.754mA   -52.29mA   -428.7uA
-780mV    -708.9uA   -21.31mA   -240uA
-720mV    -194.5uA   -5.864mA   -159.9uA
-660mV    -97.62uA   -1.274mA   -100.6uA
-600mV    -55.49uA   -286.4uA   -56.47uA
-420mV    -4.265uA   -10.7uA    -2.74uA
3.96V     0A         0A         0A
[POWER_clamp]
|Voltage   I(typ)   I(min)   I(max)
-1.98V    7.929A     7.752A     8.366A
-1.2V     1.949A     2.483A     1.628A
-1.14V    1.495A     2.081A     1.12A
-1.08V    1.044A     1.68A      633.7mA
-1.02V    613.2mA    1.282A     240.4mA
-960mV    264mA      886.2mA    47.43mA
-900mV    69.94mA    519.6mA    11.58mA
-840mV    15.1mA     237.3mA    7.049mA
-780mV    5.589mA    78.54mA    5.099mA
-720mV    3.316mA    21.56mA    3.521mA
-660mV    2.102mA    6.487mA    2.205mA
3.96V     0A         0A         0A
[Ramp]
| variable   typ   min   max
dV/dt_r  0.6672/21.0074n   0.5098/39.5382n   0.8549/10.5982n
dV/dt_f  0.7261/18.9914n   0.5286/36.9759n   0.9330/9.4226n
R_load = 0.1170k
[Rising Waveform]
R_fixture= 0.1170k
V_fixture= 0.0
V_fixture_min= 0.0
V_fixture_max= 0.0
|time   V(typ)   V(min)   V(max)
0s        403.1pV    155.9nV    14.26pV
11.41ns   -46.39uV   -19.65uV   34.1mV
19.32ns   16.19mV    11.76uV    652.4mV
25.45ns   136.5mV    339.7uV    1.117V
38.5ns    598.7mV    65.29mV    1.353V
46.5ns    838.7mV    159.1mV    1.388V
55.37ns   964.9mV    289.4mV    1.407V
74.95ns   1.062V     574.6mV    1.421V
93.01ns   1.091V     714.9mV    1.424V
207.6ns   1.112V     849.7mV    1.425V
[Rising Waveform]
R_fixture= 0.1170k
V_fixture= 1.8000
V_fixture_min= 1.7100
V_fixture_max= 1.9800
|time   V(typ)   V(min)   V(max)
0s        589.7mV    824.4mV    425mV
1.127ns   589.3mV    824.4mV    516mV
1.229ns   590.4mV    824.4mV    673.6mV
1.467ns   625.1mV    824.4mV    1.444V
1.769ns   890.8mV    824.3mV    1.786V
2.047ns   1.446V     839.2mV    1.853V
2.281ns   1.656V     892.4mV    1.891V
3.04ns    1.742V     1.562V     1.964V
3.668ns   1.776V     1.677V     1.976V
207.6ns   1.8V       1.71V      1.98V
[Falling Waveform]
R_fixture= 0.1170k
V_fixture= 0.0
V_fixture_min= 0.0
V_fixture_max= 0.0
|time   V(typ)   V(min)   V(max)
0s        1.112V     854.3mV    1.425V
989.1ps   1.114V     854.3mV    1.354V
1.12ns    1.111V     854.5mV    1.18V
1.426ns   1.028V     856.6mV    374.4mV
1.748ns   577.5mV    845.3mV    119.1mV
2.131ns   130.5mV    731.6mV    95.82mV
2.675ns   27.08mV    219.7mV    57.23mV
2.969ns   28.92mV    75.54mV    45.79mV
5.008ns   17.9mV     28.73mV    6.407mV
207.6ns   154.7nV    2.444uV    20.36nV
[Falling Waveform]
R_fixture= 0.1170k
V_fixture= 1.8000
V_fixture_min= 1.7100
V_fixture_max= 1.9800
|time   V(typ)   V(min)   V(max)
0s        1.8V       1.71V      1.98V
10.61ns   1.8V       1.71V      1.919V
13.98ns   1.795V     1.71V      1.692V
23.7ns    1.616V     1.696V     732.7mV
34.52ns   1.174V     1.612V     507mV
42.19ns   882.3mV    1.511V     468.5mV
50.15ns   750.3mV    1.381V     449.3mV
68.9ns    648.5mV    1.082V     432mV
87.52ns   615mV      951.2mV    427.1mV
207.6ns   589.9mV    829mV      425mV
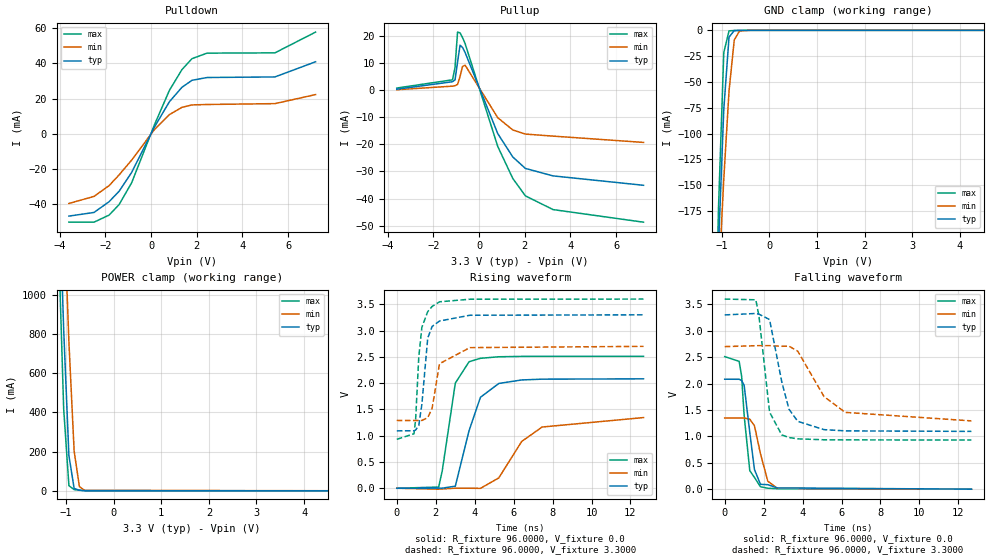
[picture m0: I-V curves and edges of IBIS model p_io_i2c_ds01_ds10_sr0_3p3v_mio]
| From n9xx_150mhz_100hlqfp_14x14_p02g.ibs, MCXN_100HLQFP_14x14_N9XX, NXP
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[Model] p_io_i2c_ds01_ds10_sr0_3p3v_mio
|   Model p_io_i2c_ds01_ds10_sr0_3p3v_mio
| This model was characterised for following simulation conditions:
| External (pad) voltage:
|   - Typ: 3.3V,   - Min: 2.7V,   - Max: 3.6V
| Library cells for typ/min/max conditions are connected as defined below:
|  pad - External Pad
|  ipp_do_lv - Core Input
|  ipp_obe_lv - Output Buffer Enable
|  IOGC - NC
|  REFH3V3 - REFH3V3
|  REFL3V3 - REFL3V3
|  ZI - NC
|  abut_ncal_vddio[1] - vddio
|  abut_ncal_vddio[2] - vddio
|  abut_ncal_vddio[3] - vssio
|  abut_ncal_vddio[4] - vddio
|  abut_ncal_vddio[5] - vddio
|  abut_ncal_vddio[6] - vssio
|  abut_pcal_vddio[1] - vssio
|  abut_pcal_vddio[2] - vssio
|  abut_pcal_vddio[3] - vddio
|  abut_pcal_vddio[4] - vssio
|  abut_pcal_vddio[5] - vssio
|  abut_pcal_vddio[6] - vddio
|  ipp_do_1p8v - ipp_do_1p8v
|  ipp_dse_lv[0] - vdd_lv
|  ipp_dse_lv[1] - 0
|  ipp_eftd_lv - NC
|  ipp_ina_mux_vddio - NC
|  ipp_ina_mux_vddio[0] - NC
|  ipp_ina_mux_vddio[1] - NC
|  ipp_ina_r0_vddio - NC
|  ipp_ina_r0a_vddio - NC
|  ipp_ina_r0b_vddio - NC
|  ipp_ina_r0c_vddio - NC
|  ipp_ina_r0d_vddio - NC
|  ipp_ina_r0e_vddio - NC
|  ipp_ina_r0f_vddio - NC
|  ipp_ina_r300_vddio - NC
|  ipp_ina_r300a_vddio - NC
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Model_type I/O
Polarity   Non-Inverting
Enable   Active-High
Vinl =   0.9900V
Vinh =   2.3100V
Vmeas =  1.6500V
Cref =   30.0000pF
Rref =   1.0000M
Vref =   3.3000V
C_comp   1.4149pF   1.3702pF   1.4746pF
|C_comp_pullup   0.5853pF   0.6307pF   0.5567pF
|C_comp_pulldown   0.7310pF   0.7416pF   0.7171pF
[Model Spec]
| variable   typ   min   max
Vinh   2.3100V   1.8900V   2.5200V
Vinl   0.9900V   0.8100V   1.0800V
[Temperature Range]   25.0000   0.1250k   -40.0000
[Voltage Range]   3.3000V   2.7000V   3.6000V
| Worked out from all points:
|   slope of the pulldown table from 0 to 0.495 V, typ, clamps not added: 40.9 ohm
|   slope of the pullup table from 0 to 0.495 V, typ, clamps not added: 47.8 ohm
|   GND clamp passes 1 mA (typ) near -0.75 V on its own axis
|   POWER clamp passes 1 mA (typ) near -0.57 V on its own axis
|   rising waveform, R_fixture 96.0000, V_fixture 0.0: 20-80 % time 890ps typ, 1.65ns min, 609ps max; typ from 0 V to 2.08 V
|   rising waveform, R_fixture 96.0000, V_fixture 3.3000: 20-80 % time 313ps typ, 387ps min, 298ps max; typ from 1.09 V to 3.3 V
|   falling waveform, R_fixture 96.0000, V_fixture 0.0: 20-80 % time 359ps typ, 459ps min, 315ps max; typ from 2.08 V to 0 V
|   falling waveform, R_fixture 96.0000, V_fixture 3.3000: 20-80 % time 744ps typ, 1.5ns min, 476ps max; typ from 3.3 V to 1.09 V
[Pulldown]
|Voltage   I(typ)   I(min)   I(max)
-3.6V     -46.61mA   -39.46mA   -50.05mA
-2.5V     -44.55mA   -35.45mA   -50.06mA
-1.84V    -38.47mA   -29.36mA   -46.05mA
-1.4V     -32.52mA   -23.26mA   -40.08mA
-850mV    -21.83mA   -14.86mA   -27.68mA
140mV     3.705mA    2.322mA    4.92mA
800mV     18.17mA    10.88mA    24.6mA
1.35V     26.36mA    15.01mA    36.38mA
1.79V     30.32mA    16.37mA    42.59mA
2.45V     31.91mA    16.62mA    45.72mA
5.42V     32.23mA    17.11mA    45.87mA
7.2V      40.82mA    22.25mA    57.64mA
[Pullup]
|Voltage   I(typ)   I(min)   I(max)
-3.6V     399uA      213.2uA    834.8uA
-1.16V    3.164mA    1.529mA    3.876mA
-1.05V    3.864mA    1.713mA    8.441mA
-940mV    10.38mA    2.174mA    21.51mA
-830mV    16.66mA    5.095mA    21.21mA
-720mV    15.81mA    8.818mA    19.46mA
-610mV    13.99mA    9.291mA    17.29mA
820mV     -16.01mA   -10.12mA   -20.75mA
1.48V     -24.65mA   -14.67mA   -32.61mA
2.03V     -28.87mA   -16.18mA   -39mA
3.24V     -31.63mA   -16.93mA   -44.08mA
7.2V      -35.1mA    -19.26mA   -48.74mA
[GND_clamp]
|Voltage   I(typ)   I(min)   I(max)
-3.6V     -4.327A    -3.181A    -5.901A
-1.18V    -358.9mA   -350.6mA   -379.3mA
-1.07V    -208.2mA   -244.2mA   -170.8mA
-960mV    -76.59mA   -144.3mA   -21.58mA
-850mV    -6.561mA   -58.74mA   -508.1uA
-740mV    -273.3uA   -9.382mA   -183.5uA
-630mV    -73.8uA    -593.1uA   -76.7uA
-410mV    -3.432uA   -9.016uA   -2.096uA
7.2V      0A         0A         0A
[POWER_clamp]
|Voltage   I(typ)   I(min)   I(max)
-3.6V     20.44A     18.76A     22.48A
-1.16V    1.647A     2.216A     1.289A
-1.05V    823.6mA    1.482A     419.2mA
-940mV    180.4mA    758.9mA    26.72mA
-830mV    12.56mA    202.9mA    6.794mA
-720mV    3.422mA    22.23mA    3.58mA
-610mV    1.373mA    2.923mA    1.344mA
7.2V      0A         0A         0A
[Ramp]
| variable   typ   min   max
dV/dt_r  1.2491/0.8902n   0.8067/1.6513n   1.5058/0.6088n
dV/dt_f  1.3238/0.7442n   0.8443/1.4969n   1.6012/0.4762n
R_load = 96.0000
[Rising Waveform]
R_fixture= 96.0000
V_fixture= 0.0
V_fixture_min= 0.0
V_fixture_max= 0.0
|time   V(typ)   V(min)   V(max)
0s        2.177nV    161nV      7.426nV
2.152ns   2.342mV    -17.29mV   22.98mV
2.336ns   1.682mV    -12.59mV   334.3mV
3.006ns   39.71mV    1.301mV    2V
3.711ns   1.095V     459.6uV    2.407V
4.297ns   1.731V     -1.672mV   2.473V
5.238ns   1.994V     196.9mV    2.502V
6.416ns   2.061V     890.7mV    2.509V
7.462ns   2.076V     1.165V     2.51V
12.67ns   2.082V     1.345V     2.51V
[Rising Waveform]
R_fixture= 96.0000
V_fixture= 3.3000
V_fixture_min= 2.7000
V_fixture_max= 3.6000
|time   V(typ)   V(min)   V(max)
0s        1.093V     1.29V      931.2mV
882.6ps   1.094V     1.29V      1.037V
968.1ps   1.108V     1.29V      1.308V
1.13ns    1.193V     1.29V      2.501V
1.288ns   1.595V     1.29V      3.061V
1.589ns   2.859V     1.344V     3.361V
1.816ns   3.079V     1.524V     3.46V
2.194ns   3.182V     2.37V      3.548V
3.754ns   3.292V     2.676V     3.597V
12.67ns   3.3V       2.7V       3.6V
[Falling Waveform]
R_fixture= 96.0000
V_fixture= 0.0
V_fixture_min= 0.0
V_fixture_max= 0.0
|time   V(typ)   V(min)   V(max)
0s        2.082V     1.348V     2.51V
742.3ps   2.081V     1.348V     2.421V
867.5ps   2.057V     1.348V     2.148V
999.4ps   1.967V     1.349V     1.394V
1.288ns   1.075V     1.326V     350.6mV
1.528ns   371.4mV    1.201V     221.8mV
1.837ns   92.09mV    670.4mV    46.24mV
2.215ns   84.77mV    150mV      17.73mV
2.701ns   23.3mV     16.8mV     8.315mV
12.67ns   5.747uV    52.34uV    1.012uV
[Falling Waveform]
R_fixture= 96.0000
V_fixture= 3.3000
V_fixture_min= 2.7000
V_fixture_max= 3.6000
|time   V(typ)   V(min)   V(max)
0s        3.3V       2.7V       3.6V
1.601ns   3.327V     2.716V     3.586V
1.761ns   3.313V     2.718V     3.273V
2.305ns   3.212V     2.718V     1.458V
2.929ns   2.036V     2.706V     1.028V
3.301ns   1.514V     2.708V     977.8mV
3.754ns   1.284V     2.612V     952.7mV
5.104ns   1.127V     1.751V     935.3mV
6.194ns   1.104V     1.454V     933mV
12.67ns   1.094V     1.293V     931.3mV
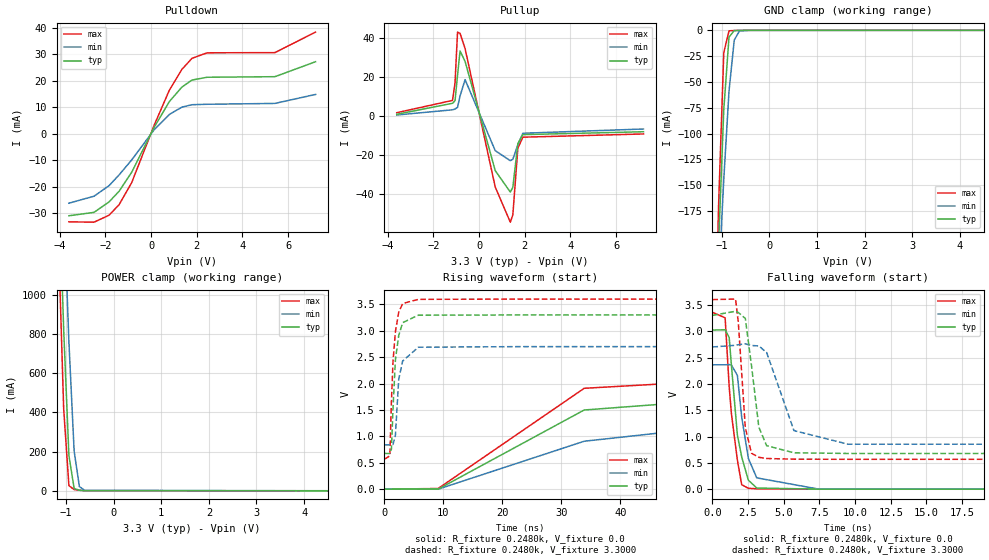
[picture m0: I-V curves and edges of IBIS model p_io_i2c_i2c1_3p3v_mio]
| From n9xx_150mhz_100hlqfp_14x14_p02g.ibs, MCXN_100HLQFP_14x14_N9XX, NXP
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[Model] p_io_i2c_i2c1_3p3v_mio
|   Model p_io_i2c_i2c1_3p3v_mio
| This model was characterised for following simulation conditions:
| External (pad) voltage:
|   - Typ: 3.3V,   - Min: 2.7V,   - Max: 3.6V
| Library cells for typ/min/max conditions are connected as defined below:
|  pad - External Pad
|  ipp_do_lv - Core Input
|  ipp_obe_lv - Output Buffer Enable
|  IOGC - NC
|  REFH3V3 - REFH3V3
|  REFL3V3 - REFL3V3
|  ZI - NC
|  abut_ncal_vddio[1] - vddio
|  abut_ncal_vddio[2] - vddio
|  abut_ncal_vddio[3] - vssio
|  abut_ncal_vddio[4] - vddio
|  abut_ncal_vddio[5] - vddio
|  abut_ncal_vddio[6] - vssio
|  abut_pcal_vddio[1] - vssio
|  abut_pcal_vddio[2] - vssio
|  abut_pcal_vddio[3] - vddio
|  abut_pcal_vddio[4] - vssio
|  abut_pcal_vddio[5] - vssio
|  abut_pcal_vddio[6] - vddio
|  ipp_do_1p8v - ipp_do_1p8v
|  ipp_eftd_lv - NC
|  ipp_i2c_lv - vdd_lv
|  ipp_ina_mux_vddio - NC
|  ipp_ina_mux_vddio[0] - NC
|  ipp_ina_mux_vddio[1] - NC
|  ipp_ina_r0_vddio - NC
|  ipp_ina_r0a_vddio - NC
|  ipp_ina_r0b_vddio - NC
|  ipp_ina_r0c_vddio - NC
|  ipp_ina_r0d_vddio - NC
|  ipp_ina_r0e_vddio - NC
|  ipp_ina_r0f_vddio - NC
|  ipp_ina_r300_vddio - NC
|  ipp_ina_r300a_vddio - NC
|  ipp_ina_r300b_vddio - NC
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Model_type I/O
Polarity   Non-Inverting
Enable   Active-High
Vinl =   0.9900V
Vinh =   2.3100V
Vmeas =  1.6500V
Cref =   30.0000pF
Rref =   1.0000M
Vref =   3.3000V
C_comp   1.4149pF   1.3702pF   1.4746pF
|C_comp_pullup   0.5853pF   0.6307pF   0.5567pF
|C_comp_pulldown   0.7310pF   0.7416pF   0.7172pF
[Model Spec]
| variable   typ   min   max
Vinh   2.3100V   1.8900V   2.5200V
Vinl   0.9900V   0.8100V   1.0800V
[Temperature Range]   25.0000   0.1250k   -40.0000
[Voltage Range]   3.3000V   2.7000V   3.6000V
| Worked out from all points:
|   slope of the pulldown table from 0 to 0.495 V, typ, clamps not added: 61.3 ohm
|   slope of the pullup table from 0 to 0.495 V, typ, clamps not added: 23.9 ohm
|   GND clamp passes 1 mA (typ) near -0.75 V on its own axis
|   POWER clamp passes 1 mA (typ) near -0.57 V on its own axis
|   rising waveform, R_fixture 0.2480k, V_fixture 0.0: 20-80 % time 2.36us typ, 135ns min, 25.3us max; typ from 0 V to 3.02 V
|   rising waveform, R_fixture 0.2480k, V_fixture 3.3000: 20-80 % time 835ps typ, 798ps min, 798ps max; typ from 0.677 V to 3.3 V
|   falling waveform, R_fixture 0.2480k, V_fixture 0.0: 20-80 % time 744ps typ, 760ps min, 670ps max; typ from 3.02 V to 0 V
|   falling waveform, R_fixture 0.2480k, V_fixture 3.3000: 20-80 % time 658ps typ, 1.28ns min, 441ps max; typ from 3.3 V to 0.677 V
[Pulldown]
|Voltage   I(typ)   I(min)   I(max)
-3.6V     -30.97mA   -26.22mA   -33.25mA
-2.5V     -29.69mA   -23.6mA    -33.39mA
-1.84V    -25.73mA   -19.61mA   -30.76mA
-1.4V     -21.71mA   -15.55mA   -26.77mA
-850mV    -14.57mA   -9.915mA   -18.47mA
140mV     2.472mA    1.548mA    3.283mA
800mV     12.12mA    7.253mA    16.41mA
1.35V     17.58mA    10.01mA    24.26mA
1.79V     20.21mA    10.91mA    28.4mA
2.45V     21.27mA    11.08mA    30.48mA
5.42V     21.48mA    11.4mA     30.56mA
7.2V      27.13mA    14.79mA    38.3mA
[Pullup]
|Voltage   I(typ)   I(min)   I(max)
-3.6V     785.4uA    423.2uA    1.608mA
-1.16V    6.455mA    3.098mA    7.926mA
-1.05V    7.777mA    3.482mA    16.99mA
-940mV    20.9mA     4.372mA    43.05mA
-830mV    33.33mA    10.25mA    42.41mA
-610mV    27.98mA    18.58mA    34.56mA
710mV     -28.18mA   -17.91mA   -36.61mA
1.37V     -39.19mA   -23.06mA   -54.68mA
1.48V     -36.8mA    -22.32mA   -50.99mA
1.7V      -14.29mA   -14.88mA   -16.58mA
1.92V     -9.671mA   -8.955mA   -10.98mA
7.2V      -8.178mA   -6.77mA    -9.319mA
[GND_clamp]
|Voltage   I(typ)   I(min)   I(max)
-3.6V     -4.327A    -3.181A    -5.901A
-1.18V    -358.9mA   -350.6mA   -379.3mA
-1.07V    -208.2mA   -244.2mA   -170.8mA
-960mV    -76.59mA   -144.3mA   -21.58mA
-850mV    -6.561mA   -58.74mA   -508.1uA
-740mV    -273.3uA   -9.383mA   -183.5uA
-630mV    -73.8uA    -593.6uA   -76.7uA
-410mV    -3.432uA   -9.053uA   -2.096uA
7.2V      0A         0A         0A
[POWER_clamp]
|Voltage   I(typ)   I(min)   I(max)
-3.6V     20.44A     18.76A     22.48A
-1.16V    1.647A     2.216A     1.289A
-1.05V    823.6mA    1.482A     419.2mA
-940mV    180.4mA    758.9mA    26.72mA
-830mV    12.56mA    202.9mA    6.794mA
-720mV    3.422mA    22.23mA    3.58mA
-610mV    1.373mA    2.923mA    1.344mA
7.2V      0A         0A         0A
[Ramp]
| variable   typ   min   max
dV/dt_r  1.8122/2.3602u   1.4170/0.1352u   2.0150/25.8586u
dV/dt_f  1.5738/0.6581n   1.1168/1.2841n   1.8197/0.4405n
R_load = 0.2480k
[Rising Waveform]
R_fixture= 0.2480k
V_fixture= 0.0
V_fixture_min= 0.0
V_fixture_max= 0.0
|time   V(typ)   V(min)   V(max)
0s        3.665nV    285.8nV    12.3nV
9.113ns   743.9uV    -128uV     12.31mV
33.88ns   1.499V     907.7mV    1.91V
87.81ns   1.951V     1.565V     2.25V
292.6ns   2.018V     2.335V     2.285V
2.242us   2.226V     2.358V     2.317V
2.555us   3.014V     2.358V     2.319V
25.05us   3.02V      2.361V     2.492V
26.05us   3.02V      2.361V     3.356V
50us      3.02V      2.362V     3.358V
[Rising Waveform]
R_fixture= 0.2480k
V_fixture= 3.3000
V_fixture_min= 2.7000
V_fixture_max= 3.6000
|time   V(typ)   V(min)   V(max)
0s        677mV      838.6mV    567.1mV
914.8ps   676mV      838.6mV    631mV
1.186ns   760.1mV    838.7mV    1.671V
1.458ns   1.539V     846.9mV    2.426V
1.861ns   2.453V     1.024V     2.983V
2.422ns   2.91V      2.079V     3.35V
3.086ns   3.153V     2.427V     3.515V
5.754ns   3.295V     2.688V     3.595V
22.4ns    3.299V     2.699V     3.599V
50us      3.3V       2.7V       3.6V
[Falling Waveform]
R_fixture= 0.2480k
V_fixture= 0.0
V_fixture_min= 0.0
V_fixture_max= 0.0
|time   V(typ)   V(min)   V(max)
0s        3.021V     2.362V     3.359V
894.8ps   3.027V     2.362V     3.254V
1.178ns   2.881V     2.366V     1.948V
1.332ns   2.364V     2.358V     1.441V
1.753ns   1.027V     2.161V     553mV
2.055ns   613mV      1.371V     84.7mV
2.523ns   170.1mV    584.2mV    17.04mV
3.112ns   21.76mV    214.5mV    6.673mV
7.436ns   324.1uV    1.676mV    95.61uV
50us      7.087nV    285.7nV    7.39nV
[Falling Waveform]
R_fixture= 0.2480k
V_fixture= 3.3000
V_fixture_min= 2.7000
V_fixture_max= 3.6000
|time   V(typ)   V(min)   V(max)
0s        3.3V       2.7V       3.6V
1.624ns   3.378V     2.732V     3.61V
1.819ns   3.356V     2.743V     3.169V
2.308ns   3.242V     2.759V     1.169V
2.744ns   2.344V     2.728V     681.8mV
3.257ns   1.177V     2.72V      604.6mV
3.803ns   825.9mV    2.595V     582.3mV
5.717ns   690.7mV    1.112V     569.3mV
9.508ns   678.1mV    853.7mV    567.2mV
50us      677mV      838.6mV    567.1mV
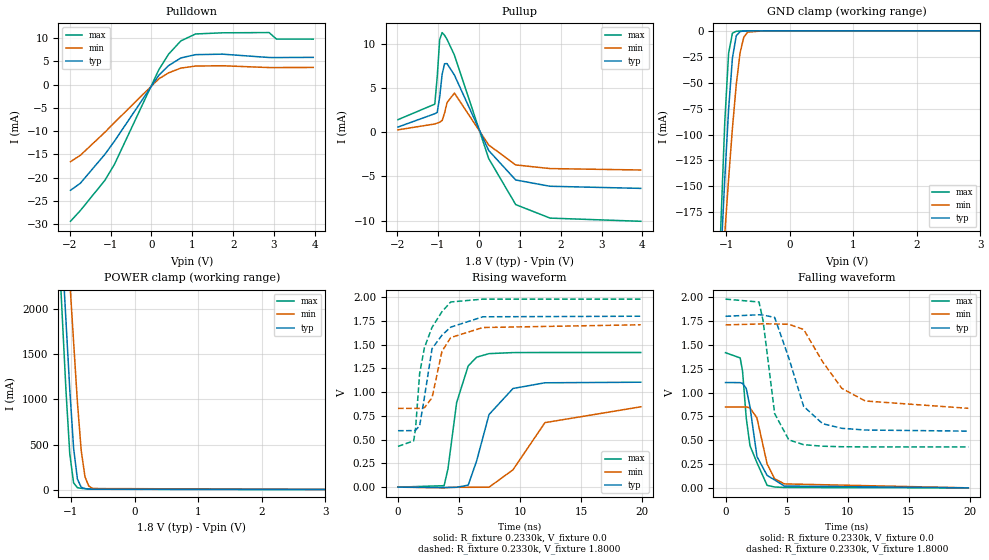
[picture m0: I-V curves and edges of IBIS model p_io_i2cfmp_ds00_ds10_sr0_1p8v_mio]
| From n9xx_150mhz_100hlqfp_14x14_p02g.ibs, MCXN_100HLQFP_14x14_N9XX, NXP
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[Model] p_io_i2cfmp_ds00_ds10_sr0_1p8v_mio
|   Model p_io_i2cfmp_ds00_ds10_sr0_1p8v_mio
| This model was characterised for following simulation conditions:
| External (pad) voltage:
|   - Typ: 1.8V,   - Min: 1.71V,   - Max: 1.98V
| Library cells for typ/min/max conditions are connected as defined below:
|  pad - External Pad
|  ipp_do_lv - Core Input
|  ipp_obe_lv - Output Buffer Enable
|  IOGC - NC
|  REFH3V3 - REFH3V3
|  REFL3V3 - REFL3V3
|  ZI - NC
|  abut_ncal_vddio[1] - vssio vddio vddio
|  abut_ncal_vddio[2] - vddio vddio vssio
|  abut_ncal_vddio[3] - vddio
|  abut_ncal_vddio[4] - vssio vddio vddio
|  abut_ncal_vddio[5] - vddio vddio vssio
|  abut_ncal_vddio[6] - vddio
|  abut_pcal_vddio[1] - vssio
|  abut_pcal_vddio[2] - vddio vssio vddio
|  abut_pcal_vddio[3] - vssio
|  abut_pcal_vddio[4] - vssio
|  abut_pcal_vddio[5] - vddio vssio vddio
|  abut_pcal_vddio[6] - vssio
|  ipp_do_1p8v - ipp_do_1p8v
|  ipp_dse_lv[0] - 0
|  ipp_dse_lv[1] - 0
|  ipp_eftd_lv - NC
|  ipp_ina_mux_vddio - NC
|  ipp_ina_mux_vddio[0] - NC
|  ipp_ina_mux_vddio[1] - NC
|  ipp_ina_r0_vddio - NC
|  ipp_ina_r0a_vddio - NC
|  ipp_ina_r0b_vddio - NC
|  ipp_ina_r0c_vddio - NC
|  ipp_ina_r0d_vddio - NC
|  ipp_ina_r0e_vddio - NC
|  ipp_ina_r0f_vddio - NC
|  ipp_ina_r300_vddio - NC
|  ipp_ina_r300a_vddio - NC
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Model_type I/O
Polarity   Non-Inverting
Enable   Active-High
Vinl =   0.5400V
Vinh =   1.2600V
Vmeas =  0.9000V
Cref =   30.0000pF
Rref =   1.0000M
Vref =   1.8000V
C_comp   1.7515pF   1.7218pF   1.7928pF
|C_comp_pullup   0.7570pF   0.8224pF   0.7007pF
|C_comp_pulldown   0.8806pF   0.8514pF   0.9098pF
[Model Spec]
| variable   typ   min   max
Vinh   1.2600V   1.1970V   1.3860V
Vinl   0.5400V   0.5130V   0.5940V
[Temperature Range]   25.0000   0.1250k   -40.0000
[Voltage Range]   1.8000V   1.7100V   1.9800V
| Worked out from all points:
|   slope of the pulldown table from 0 to 0.27 V, typ, clamps not added: 94.2 ohm
|   slope of the pullup table from 0 to 0.27 V, typ, clamps not added: 117 ohm
|   GND clamp passes 1 mA (typ) near -0.78 V on its own axis
|   POWER clamp passes 1 mA (typ) near -0.53 V on its own axis
|   rising waveform, R_fixture 0.2330k, V_fixture 0.0: 20-80 % time 1.83ns typ, 2.64ns min, 1.11ns max; typ from 0 V to 1.1 V
|   rising waveform, R_fixture 0.2330k, V_fixture 1.8000: 20-80 % time 1.17ns typ, 1.05ns min, 1.24ns max; typ from 0.594 V to 1.8 V
|   falling waveform, R_fixture 0.2330k, V_fixture 0.0: 20-80 % time 881ps typ, 948ps min, 1.04ns max; typ from 1.1 V to 0 V
|   falling waveform, R_fixture 0.2330k, V_fixture 1.8000: 20-80 % time 1.66ns typ, 2.75ns min, 939ps max; typ from 1.8 V to 0.595 V
[Pulldown]
|Voltage   I(typ)   I(min)   I(max)
-1.98V    -22.71mA   -16.55mA   -29.37mA
-1.74V    -21.21mA   -15.2mA    -27.08mA
-1.14V    -15mA      -10.25mA   -20.59mA
-900mV    -12.1mA    -8.114mA   -17.06mA
180mV     2.012mA    1.246mA    3.179mA
420mV     4.088mA    2.535mA    6.549mA
720mV     5.743mA    3.561mA    9.405mA
1.08V     6.453mA    4.005mA    10.9mA
1.74V     6.558mA    4.067mA    11.15mA
2.88V     5.839mA    3.678mA    11.2mA
3.06V     5.829mA    3.677mA    9.802mA
3.96V     5.871mA    3.703mA    9.79mA
[Pullup]
|Voltage   I(typ)   I(min)   I(max)
-1.98V    578.3uA    262.5uA    1.413mA
-1.08V    2.082mA    925.3uA    3.166mA
-1.02V    2.24mA     1.021mA    6.246mA
-960mV    3.967mA    1.121mA    10.46mA
-900mV    6.538mA    1.314mA    11.26mA
-840mV    7.737mA    2.17mA     10.95mA
-780mV    7.751mA    3.329mA    10.49mA
-600mV    6.46mA     4.424mA    8.721mA
240mV     -2.08mA    -1.452mA   -2.99mA
900mV     -5.408mA   -3.707mA   -8.19mA
1.74V     -6.118mA   -4.118mA   -9.719mA
3.96V     -6.358mA   -4.279mA   -10.08mA
[GND_clamp]
|Voltage   I(typ)   I(min)   I(max)
-1.98V    -1.571A    -1.243A    -2.046A
-1.14V    -296.8mA   -307.7mA   -291.9mA
-1.08V    -217.1mA   -250.6mA   -183.3mA
-1.02V    -142mA     -195.3mA   -87.29mA
-960mV    -75.42mA   -142.6mA   -21.4mA
-900mV    -26.21mA   -93.87mA   -2.23mA
-840mV    -4.776mA   -51.84mA   -446.5uA
-780mV    -725.4uA   -21.22mA   -243.9uA
-720mV    -200uA     -5.88mA    -159.3uA
-660mV    -98.47uA   -1.291mA   -98.82uA
-420mV    -3.926uA   -10.95uA   -2.45uA
3.96V     0A         0A         0A
[POWER_clamp]
|Voltage   I(typ)   I(min)   I(max)
-1.98V    13.51A     13.25A     14.01A
-1.2V     3.414A     4.356A     2.802A
-1.14V    2.644A     3.675A     1.949A
-1.08V    1.876A     2.995A     1.103A
-1.02V    1.113A     2.317A     397.9mA
-960mV    462.1mA    1.641A     75.38mA
-900mV    117mA      972.3mA    21.31mA
-840mV    26.38mA    432.6mA    13.76mA
-780mV    10.65mA    139.4mA    9.996mA
-720mV    6.506mA    38.48mA    6.892mA
-660mV    4.142mA    12.01mA    4.303mA
3.96V     0A         0A         0A
[Ramp]
| variable   typ   min   max
dV/dt_r  0.6631/1.8338n   0.5075/2.6377n   0.8506/1.1087n
dV/dt_f  0.7229/1.6628n   0.5253/2.7497n   0.9305/0.9391n
R_load = 0.2330k
[Rising Waveform]
R_fixture= 0.2330k
V_fixture= 0.0
V_fixture_min= 0.0
V_fixture_max= 0.0
|time   V(typ)   V(min)   V(max)
0s        1.278nV    605.2nV    30.99pV
3.779ns   -3.603mV   -7.561mV   15.37mV
4.096ns   -2.764mV   -4.022mV   193.6mV
4.805ns   -1.721mV   -1.2mV     890.6mV
5.753ns   20.89mV    -1.695mV   1.277V
6.448ns   278.6mV    -1.21mV    1.369V
7.46ns    765.1mV    -766.6uV   1.406V
9.423ns   1.039V     183mV      1.417V
12.04ns   1.099V     679.3mV    1.418V
19.89ns   1.105V     845.9mV    1.418V
[Rising Waveform]
R_fixture= 0.2330k
V_fixture= 1.8000
V_fixture_min= 1.7100
V_fixture_max= 1.9800
|time   V(typ)   V(min)   V(max)
0s        594.4mV    829.2mV    429mV
1.285ns   595.1mV    829.3mV    487.6mV
1.439ns   599.5mV    829.3mV    614.3mV
1.775ns   647.3mV    829.3mV    1.197V
2.164ns   944.5mV    836.7mV    1.468V
2.789ns   1.458V     940.7mV    1.683V
3.601ns   1.6V       1.429V     1.847V
4.318ns   1.685V     1.575V     1.95V
6.956ns   1.794V     1.681V     1.98V
19.89ns   1.8V       1.71V      1.98V
[Falling Waveform]
R_fixture= 0.2330k
V_fixture= 0.0
V_fixture_min= 0.0
V_fixture_max= 0.0
|time   V(typ)   V(min)   V(max)
0s        1.105V     848.6mV    1.418V
1.202ns   1.104V     847.9mV    1.363V
1.396ns   1.096V     848.3mV    1.225V
1.699ns   1.043V     848.3mV    733.5mV
2.004ns   850.9mV    839.2mV    443.1mV
2.576ns   328.7mV    734mV      264.2mV
3.408ns   130.4mV    251.1mV    26.41mV
4.011ns   84mV       96.54mV    9.23mV
4.819ns   19.14mV    41.52mV    4.056mV
19.89ns   5.879uV    68.74uV    368.8nV
[Falling Waveform]
R_fixture= 0.2330k
V_fixture= 1.8000
V_fixture_min= 1.7100
V_fixture_max= 1.9800
|time   V(typ)   V(min)   V(max)
0s        1.8V       1.71V      1.98V
2.745ns   1.816V     1.719V     1.95V
3.071ns   1.813V     1.722V     1.758V
4.026ns   1.788V     1.719V     779.4mV
5.187ns   1.362V     1.716V     503.1mV
6.4ns     855.5mV    1.662V     453mV
7.955ns   673.1mV    1.323V     436.9mV
9.529ns   624.9mV    1.044V     431.5mV
11.45ns   606.7mV    911.3mV    429.7mV
19.89ns   595.1mV    834.5mV    429.1mV
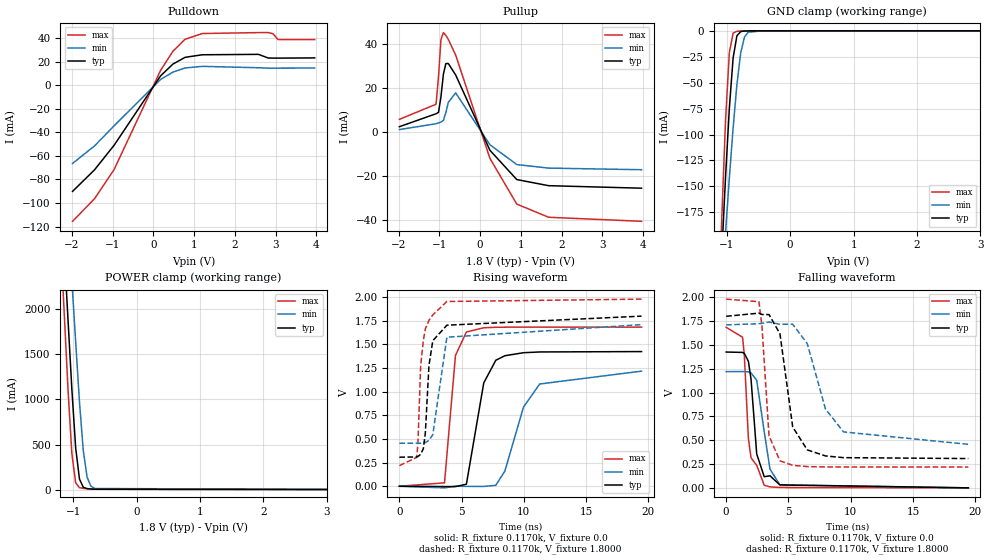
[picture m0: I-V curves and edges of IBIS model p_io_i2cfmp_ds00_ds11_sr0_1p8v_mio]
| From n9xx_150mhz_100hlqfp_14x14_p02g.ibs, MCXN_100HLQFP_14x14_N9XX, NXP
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[Model] p_io_i2cfmp_ds00_ds11_sr0_1p8v_mio
|   Model p_io_i2cfmp_ds00_ds11_sr0_1p8v_mio
| This model was characterised for following simulation conditions:
| External (pad) voltage:
|   - Typ: 1.8V,   - Min: 1.71V,   - Max: 1.98V
| Library cells for typ/min/max conditions are connected as defined below:
|  pad - External Pad
|  ipp_do_lv - Core Input
|  ipp_obe_lv - Output Buffer Enable
|  IOGC - NC
|  REFH3V3 - REFH3V3
|  REFL3V3 - REFL3V3
|  ZI - NC
|  abut_ncal_vddio[1] - vssio vddio vddio
|  abut_ncal_vddio[2] - vddio vddio vssio
|  abut_ncal_vddio[3] - vddio
|  abut_ncal_vddio[4] - vssio vddio vddio
|  abut_ncal_vddio[5] - vddio vddio vssio
|  abut_ncal_vddio[6] - vddio
|  abut_pcal_vddio[1] - vssio
|  abut_pcal_vddio[2] - vddio vssio vddio
|  abut_pcal_vddio[3] - vssio
|  abut_pcal_vddio[4] - vssio
|  abut_pcal_vddio[5] - vddio vssio vddio
|  abut_pcal_vddio[6] - vssio
|  ipp_do_1p8v - ipp_do_1p8v
|  ipp_dse_lv[0] - 0
|  ipp_dse_lv[1] - vdd_lv
|  ipp_eftd_lv - NC
|  ipp_ina_mux_vddio - NC
|  ipp_ina_mux_vddio[0] - NC
|  ipp_ina_mux_vddio[1] - NC
|  ipp_ina_r0_vddio - NC
|  ipp_ina_r0a_vddio - NC
|  ipp_ina_r0b_vddio - NC
|  ipp_ina_r0c_vddio - NC
|  ipp_ina_r0d_vddio - NC
|  ipp_ina_r0e_vddio - NC
|  ipp_ina_r0f_vddio - NC
|  ipp_ina_r300_vddio - NC
|  ipp_ina_r300a_vddio - NC
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Model_type I/O
Polarity   Non-Inverting
Enable   Active-High
Vinl =   0.5400V
Vinh =   1.2600V
Vmeas =  0.9000V
Cref =   30.0000pF
Rref =   1.0000M
Vref =   1.8000V
C_comp   1.7515pF   1.7218pF   1.7928pF
|C_comp_pullup   0.7559pF   0.8215pF   0.6995pF
|C_comp_pulldown   0.8817pF   0.8523pF   0.9111pF
[Model Spec]
| variable   typ   min   max
Vinh   1.2600V   1.1970V   1.3860V
Vinl   0.5400V   0.5130V   0.5940V
[Temperature Range]   25.0000   0.1250k   -40.0000
[Voltage Range]   1.8000V   1.7100V   1.9800V
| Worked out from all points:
|   slope of the pulldown table from 0 to 0.27 V, typ, clamps not added: 23.6 ohm
|   slope of the pullup table from 0 to 0.27 V, typ, clamps not added: 29.3 ohm
|   GND clamp passes 1 mA (typ) near -0.78 V on its own axis
|   POWER clamp passes 1 mA (typ) near -0.53 V on its own axis
|   rising waveform, R_fixture 0.1170k, V_fixture 0.0: 20-80 % time 1.01ns typ, 1.84ns min, 578ps max; typ from 0 V to 1.43 V
|   rising waveform, R_fixture 0.1170k, V_fixture 1.8000: 20-80 % time 514ps typ, 608ps min, 503ps max; typ from 0.307 V to 1.8 V
|   falling waveform, R_fixture 0.1170k, V_fixture 0.0: 20-80 % time 543ps typ, 697ps min, 481ps max; typ from 1.43 V to 0 V
|   falling waveform, R_fixture 0.1170k, V_fixture 1.8000: 20-80 % time 961ps typ, 1.81ns min, 505ps max; typ from 1.8 V to 0.307 V
[Pulldown]
|Voltage   I(typ)   I(min)   I(max)
-1.98V    -90.09mA   -66.35mA   -115.5mA
-1.44V    -71.75mA   -51.46mA   -96.31mA
-960mV    -50.89mA   -34.36mA   -71.45mA
180mV     8.022mA    4.974mA    12.66mA
480mV     17.96mA    11.14mA    28.86mA
780mV     23.75mA    14.73mA    39.1mA
1.2V      25.92mA    16.08mA    43.96mA
2.58V     26.28mA    14.91mA    44.75mA
2.82V     23.17mA    14.57mA    44.78mA
2.94V     23.1mA     14.56mA    43.77mA
3.06V     23.08mA    14.57mA    38.82mA
3.96V     23.26mA    14.67mA    38.81mA
[Pullup]
|Voltage   I(typ)   I(min)   I(max)
-1.98V    2.336mA    1.052mA    5.673mA
-1.08V    8.21mA     3.673mA    12.52mA
-1.02V    8.847mA    4.048mA    25.01mA
-960mV    15.85mA    4.437mA    41.87mA
-900mV    26.16mA    5.212mA    44.99mA
-840mV    30.93mA    8.666mA    43.74mA
-780mV    30.97mA    13.31mA    41.91mA
-600mV    25.81mA    17.68mA    34.83mA
240mV     -8.314mA   -5.805mA   -11.95mA
900mV     -21.61mA   -14.82mA   -32.73mA
1.68V     -24.38mA   -16.42mA   -38.69mA
3.96V     -25.52mA   -17.15mA   -40.52mA
[GND_clamp]
|Voltage   I(typ)   I(min)   I(max)
-1.98V    -1.571A    -1.243A    -2.046A
-1.14V    -296.8mA   -307.7mA   -291.9mA
-1.08V    -217.1mA   -250.6mA   -183.3mA
-1.02V    -142mA     -195.3mA   -87.29mA
-960mV    -75.42mA   -142.6mA   -21.4mA
-900mV    -26.21mA   -93.87mA   -2.23mA
-840mV    -4.776mA   -51.84mA   -446.5uA
-780mV    -725.4uA   -21.22mA   -243.9uA
-720mV    -200uA     -5.88mA    -159.3uA
-660mV    -98.47uA   -1.291mA   -98.82uA
-420mV    -3.926uA   -10.95uA   -2.45uA
3.96V     0A         0A         0A
[POWER_clamp]
|Voltage   I(typ)   I(min)   I(max)
-1.98V    13.51A     13.25A     14.01A
-1.2V     3.414A     4.356A     2.802A
-1.14V    2.644A     3.675A     1.949A
-1.08V    1.876A     2.995A     1.103A
-1.02V    1.113A     2.317A     397.9mA
-960mV    462.1mA    1.641A     75.38mA
-900mV    117mA      972.3mA    21.31mA
-840mV    26.38mA    432.6mA    13.76mA
-780mV    10.65mA    139.4mA    9.996mA
-720mV    6.506mA    38.48mA    6.892mA
-660mV    4.142mA    12.01mA    4.303mA
3.96V     0A         0A         0A
[Ramp]
| variable   typ   min   max
dV/dt_r  0.8549/1.0129n   0.7305/1.8387n   1.0105/0.5779n
dV/dt_f  0.8956/0.9609n   0.7521/1.8087n   1.0571/0.5054n
R_load = 0.1170k
[Rising Waveform]
R_fixture= 0.1170k
V_fixture= 0.0
V_fixture_min= 0.0
V_fixture_max= 0.0
|time   V(typ)   V(min)   V(max)
0s        426.8pV    187.1nV    11.16pV
3.626ns   -3.307mV   -17.06mV   36.04mV
4.505ns   -3.576mV   241.1uV    1.384V
5.384ns   21.65mV    -1.159mV   1.632V
6.778ns   1.093V     -2.072mV   1.677V
7.744ns   1.333V     9.84mV     1.682V
8.471ns   1.381V     159.4mV    1.683V
9.973ns   1.413V     838.2mV    1.684V
11.27ns   1.421V     1.082V     1.684V
19.45ns   1.425V     1.218V     1.684V
[Rising Waveform]
R_fixture= 0.1170k
V_fixture= 1.8000
V_fixture_min= 1.7100
V_fixture_max= 1.9800
|time   V(typ)   V(min)   V(max)
0s        307.4mV    455.1mV    218.1mV
1.393ns   310.1mV    455.1mV    305.4mV
1.492ns   314.6mV    455mV      454.5mV
1.709ns   337.7mV    454.9mV    1.275V
1.922ns   396.6mV    457mV      1.54V
2.085ns   561.9mV    462mV      1.663V
2.377ns   1.278V     485.7mV    1.756V
2.685ns   1.54V      545.7mV    1.813V
3.817ns   1.704V     1.577V     1.955V
19.45ns   1.8V       1.71V      1.98V
[Falling Waveform]
R_fixture= 0.1170k
V_fixture= 0.0
V_fixture_min= 0.0
V_fixture_max= 0.0
|time   V(typ)   V(min)   V(max)
0s        1.425V     1.219V     1.684V
1.319ns   1.421V     1.22V      1.58V
1.46ns    1.409V     1.22V      1.386V
1.781ns   1.329V     1.217V     522.4mV
1.995ns   1.142V     1.206V     315.6mV
2.453ns   354.8mV    1.128V     236.2mV
3.057ns   116.6mV    587.7mV    27.26mV
3.52ns    126.9mV    195.9mV    10.34mV
4.313ns   30.59mV    32.08mV    3.622mV
19.45ns   1.977uV    29.04uV    103.1nV
[Falling Waveform]
R_fixture= 0.1170k
V_fixture= 1.8000
V_fixture_min= 1.7100
V_fixture_max= 1.9800
|time   V(typ)   V(min)   V(max)
0s        1.8V       1.71V      1.98V
2.633ns   1.833V     1.722V     1.953V
2.872ns   1.819V     1.726V     1.699V
3.441ns   1.818V     1.74V      545.3mV
4.319ns   1.616V     1.716V     283.7mV
5.344ns   638.3mV    1.717V     236.2mV
6.514ns   398.3mV    1.513V     223.4mV
7.974ns   335mV      827.6mV    219.4mV
9.428ns   316.9mV    586.8mV    218.5mV
19.45ns   307.4mV    456.5mV    218.1mV
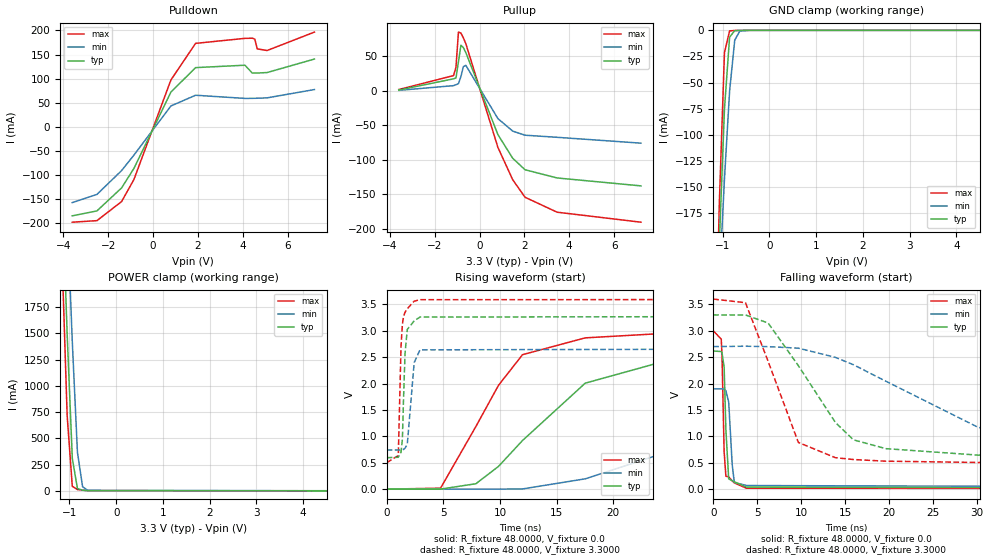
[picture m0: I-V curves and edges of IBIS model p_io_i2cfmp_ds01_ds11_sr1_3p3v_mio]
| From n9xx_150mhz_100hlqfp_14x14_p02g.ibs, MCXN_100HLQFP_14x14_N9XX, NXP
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[Model] p_io_i2cfmp_ds01_ds11_sr1_3p3v_mio
|   Model p_io_i2cfmp_ds01_ds11_sr1_3p3v_mio
| This model was characterised for following simulation conditions:
| External (pad) voltage:
|   - Typ: 3.3V,   - Min: 2.7V,   - Max: 3.6V
| Library cells for typ/min/max conditions are connected as defined below:
|  pad - External Pad
|  ipp_do_lv - Core Input
|  ipp_obe_lv - Output Buffer Enable
|  IOGC - NC
|  REFH3V3 - REFH3V3
|  REFL3V3 - REFL3V3
|  ZI - NC
|  abut_ncal_vddio[1] - vddio
|  abut_ncal_vddio[2] - vddio
|  abut_ncal_vddio[3] - vssio
|  abut_ncal_vddio[4] - vddio
|  abut_ncal_vddio[5] - vddio
|  abut_ncal_vddio[6] - vssio
|  abut_pcal_vddio[1] - vssio
|  abut_pcal_vddio[2] - vssio
|  abut_pcal_vddio[3] - vddio
|  abut_pcal_vddio[4] - vssio
|  abut_pcal_vddio[5] - vssio
|  abut_pcal_vddio[6] - vddio
|  ipp_do_1p8v - ipp_do_1p8v
|  ipp_dse_lv[0] - vdd_lv
|  ipp_dse_lv[1] - vdd_lv
|  ipp_eftd_lv - NC
|  ipp_ina_mux_vddio - NC
|  ipp_ina_mux_vddio[0] - NC
|  ipp_ina_mux_vddio[1] - NC
|  ipp_ina_r0_vddio - NC
|  ipp_ina_r0a_vddio - NC
|  ipp_ina_r0b_vddio - NC
|  ipp_ina_r0c_vddio - NC
|  ipp_ina_r0d_vddio - NC
|  ipp_ina_r0e_vddio - NC
|  ipp_ina_r0f_vddio - NC
|  ipp_ina_r300_vddio - NC
|  ipp_ina_r300a_vddio - NC
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Model_type I/O
Polarity   Non-Inverting
Enable   Active-High
Vinl =   0.9900V
Vinh =   2.3100V
Vmeas =  1.6500V
Cref =   30.0000pF
Rref =   1.0000M
Vref =   3.3000V
C_comp   1.7403pF   1.7015pF   1.7922pF
|C_comp_pullup   0.6937pF   0.7575pF   0.6565pF
|C_comp_pulldown   0.9333pF   0.9182pF   0.9324pF
[Model Spec]
| variable   typ   min   max
Vinh   2.3100V   1.8900V   2.5200V
Vinl   0.9900V   0.8100V   1.0800V
[Temperature Range]   25.0000   0.1250k   -40.0000
[Voltage Range]   3.3000V   2.7000V   3.6000V
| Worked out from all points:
|   slope of the pulldown table from 0 to 0.495 V, typ, clamps not added: 10.3 ohm
|   slope of the pullup table from 0 to 0.495 V, typ, clamps not added: 12 ohm
|   GND clamp passes 1 mA (typ) near -0.75 V on its own axis
|   POWER clamp passes 1 mA (typ) near -0.52 V on its own axis
|   rising waveform, R_fixture 48.0000, V_fixture 0.0: 20-80 % time 7.87ns typ, 17.5ns min, 4.73ns max; typ from 0 V to 2.62 V
|   rising waveform, R_fixture 48.0000, V_fixture 3.3000: 20-80 % time 257ps typ, 344ps min, 222ps max; typ from 0.595 V to 3.3 V
|   falling waveform, R_fixture 48.0000, V_fixture 0.0: 20-80 % time 286ps typ, 376ps min, 252ps max; typ from 2.62 V to 0 V
|   falling waveform, R_fixture 48.0000, V_fixture 3.3000: 20-80 % time 6.36ns typ, 14.3ns min, 3.83ns max; typ from 3.3 V to 0.595 V
[Pulldown]
|Voltage   I(typ)   I(min)   I(max)
-3.6V     -184.6mA   -157.2mA   -197.8mA
-2.5V     -174.4mA   -140.2mA   -194.6mA
-1.4V     -126.7mA   -90.76mA   -155mA
-850mV    -86.25mA   -58.63mA   -109.3mA
800mV     72.05mA    43.26mA    97.24mA
1.9V      122.8mA    65.52mA    173.1mA
4.1V      127.8mA    58.94mA    183.5mA
4.43V     111.5mA    59.09mA    183.8mA
4.54V     111.5mA    59.18mA    181.9mA
4.65V     111.6mA    59.29mA    161.7mA
5.09V     112.6mA    60.08mA    158.3mA
7.2V      140.6mA    77.33mA    196.5mA
[Pullup]
|Voltage   I(typ)   I(min)   I(max)
-3.6V     1.234mA    737.3uA    1.918mA
-1.16V    17.44mA    7.57mA     22.18mA
-1.05V    18.81mA    8.961mA    34.26mA
-940mV    42.21mA    10.4mA     85.31mA
-830mV    66.21mA    20.76mA    83.9mA
-720mV    62.74mA    35.25mA    76.97mA
-610mV    55.53mA    37mA       68.37mA
820mV     -63.53mA   -40.29mA   -82.06mA
1.48V     -97.81mA   -58.39mA   -129mA
2.03V     -114.5mA   -64.35mA   -154.4mA
3.46V     -126.4mA   -67.4mA    -176.1mA
7.2V      -137.9mA   -75.9mA    -190.6mA
[GND_clamp]
|Voltage   I(typ)   I(min)   I(max)
-3.6V     -4.377A    -3.283A    -5.855A
-1.18V    -351.7mA   -346.5mA   -367.9mA
-1.07V    -204.2mA   -241.2mA   -166.2mA
-960mV    -75.42mA   -142.6mA   -21.4mA
-850mV    -6.575mA   -58.21mA   -529.8uA
-740mV    -281.6uA   -9.383mA   -183.8uA
-630mV    -73.66uA   -605.1uA   -74.76uA
-410mV    -3.148uA   -9.219uA   -1.868uA
7.2V      0A         0A         0A
[POWER_clamp]
|Voltage   I(typ)   I(min)   I(max)
-3.6V     34.56A     31.8A      37.41A
-1.16V    2.902A     3.904A     2.233A
-1.05V    1.495A     2.658A     715.5mA
-940mV    310.6mA    1.419A     44.07mA
-830mV    22.38mA    368.3mA    13.28mA
-720mV    6.713mA    39.84mA    7.005mA
-610mV    2.702mA    5.591mA    2.612mA
7.2V      0A         0A         0A
[Ramp]
| variable   typ   min   max
dV/dt_r  1.5700/7.8662n   1.1374/17.3917n   1.8003/4.7288n
dV/dt_f  1.6228/6.3641n   1.1745/14.2772n   1.8605/3.8349n
R_load = 48.0000
[Rising Waveform]
R_fixture= 48.0000
V_fixture= 0.0
V_fixture_min= 0.0
V_fixture_max= 0.0
|time   V(typ)   V(min)   V(max)
0s        1.18nV     98.79nV    3.846nV
4.754ns   -284.8uV   -1.126mV   17.31mV
7.878ns   102.1mV    -92.84uV   1.187V
9.866ns   429.1mV    361.3uV    1.964V
11.99ns   920.1mV    3.159mV    2.546V
17.53ns   2.007V     194.7mV    2.865V
24.37ns   2.413V     674.8mV    2.948V
34.93ns   2.543V     1.396V     2.985V
43.91ns   2.581V     1.655V     2.994V
135.1ns   2.617V     1.896V     3.001V
[Rising Waveform]
R_fixture= 48.0000
V_fixture= 3.3000
V_fixture_min= 2.7000
V_fixture_max= 3.6000
|time   V(typ)   V(min)   V(max)
0s        595.3mV    740.4mV    499.2mV
1.024ns   603.1mV    740.4mV    635mV
1.266ns   701.1mV    740.1mV    2.71V
1.384ns   940.5mV    743.5mV    3.116V
1.482ns   1.677V     751.1mV    3.264V
1.618ns   2.568V     774.7mV    3.348V
1.819ns   3.025V     850.2mV    3.417V
2.428ns   3.187V     2.396V     3.56V
2.94ns    3.259V     2.638V     3.588V
135.1ns   3.3V       2.7V       3.6V
[Falling Waveform]
R_fixture= 48.0000
V_fixture= 0.0
V_fixture_min= 0.0
V_fixture_max= 0.0
|time   V(typ)   V(min)   V(max)
0s        2.617V     1.899V     3.001V
914.6ps   2.606V     1.9V       2.84V
1ns       2.583V     1.9V       2.521V
1.241ns   2.311V     1.895V     707.1mV
1.441ns   1.125V     1.863V     245mV
1.76ns    196.6mV    1.649V     232.8mV
2.161ns   160.3mV    462.8mV    155.5mV
2.401ns   140mV      127.4mV    118mV
3.792ns   38.69mV    68.92mV    17.61mV
135.1ns   110.9nV    3.075uV    10.13nV
[Falling Waveform]
R_fixture= 48.0000
V_fixture= 3.3000
V_fixture_min= 2.7000
V_fixture_max= 3.6000
|time   V(typ)   V(min)   V(max)
0s        3.3V       2.7V       3.6V
3.671ns   3.299V     2.707V     3.531V
6.247ns   3.147V     2.699V     2.422V
9.693ns   2.339V     2.67V      885mV
13.91ns   1.264V     2.496V     596.3mV
15.96ns   934.4mV    2.357V     561.3mV
19.65ns   767.4mV    2.045V     530.1mV
30.2ns    644.6mV    1.168V     505.3mV
38.72ns   617.8mV    936.6mV    501.3mV
135.1ns   595.3mV    742.5mV    499.2mV
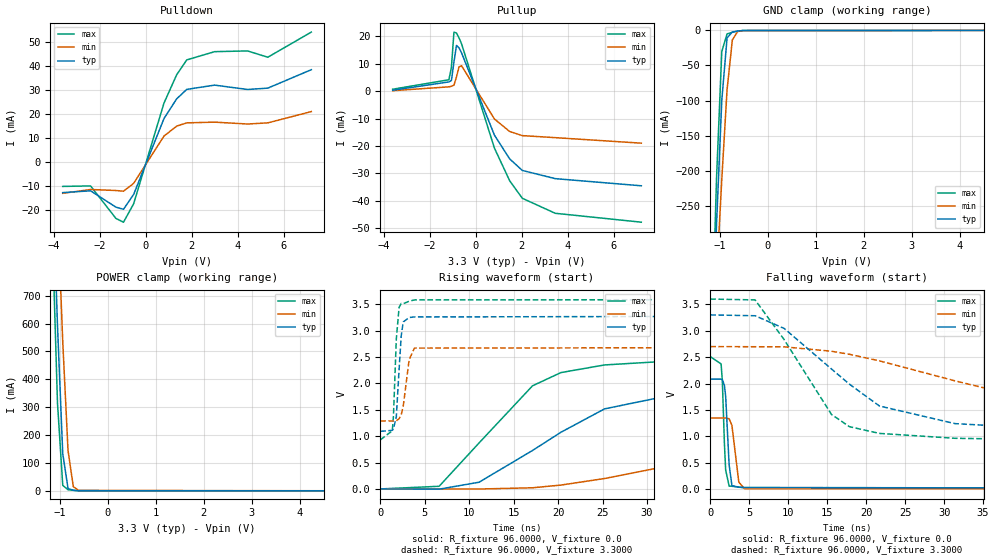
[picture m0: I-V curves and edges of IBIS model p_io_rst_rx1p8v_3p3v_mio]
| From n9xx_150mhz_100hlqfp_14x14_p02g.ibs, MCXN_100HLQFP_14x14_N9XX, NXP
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[Model] p_io_rst_rx1p8v_3p3v_mio
|   Model p_io_rst_rx1p8v_3p3v_mio
| This model was characterised for following simulation conditions:
| External (pad) voltage:
|   - Typ: 3.3V,   - Min: 2.7V,   - Max: 3.6V
| Library cells for typ/min/max conditions are connected as defined below:
|  pad - External Pad
|  ipp_do_lv - Core Input
|  ipp_obe_lv - Output Buffer Enable
|  IOGC - NC
|  REFH3V3 - REFH3V3
|  REFL3V3 - REFL3V3
|  ZI - NC
|  abut_ncal_vddio[1] - vddio
|  abut_ncal_vddio[2] - vddio
|  abut_ncal_vddio[3] - vssio
|  abut_ncal_vddio[4] - vddio
|  abut_ncal_vddio[5] - vddio
|  abut_ncal_vddio[6] - vssio
|  abut_pcal_vddio[1] - vssio
|  abut_pcal_vddio[2] - vssio
|  abut_pcal_vddio[3] - vddio
|  abut_pcal_vddio[4] - vssio
|  abut_pcal_vddio[5] - vssio
|  abut_pcal_vddio[6] - vddio
|  ipp_do_1p8v - ipp_do_1p8v
|  ipp_eftd_lv - NC
|  ipp_ina_mux_vddio - NC
|  ipp_ina_mux_vddio[0] - NC
|  ipp_ina_mux_vddio[1] - NC
|  ipp_ina_r0_vddio - NC
|  ipp_ina_r0a_vddio - NC
|  ipp_ina_r0b_vddio - NC
|  ipp_ina_r0c_vddio - NC
|  ipp_ina_r0d_vddio - NC
|  ipp_ina_r0e_vddio - NC
|  ipp_ina_r0f_vddio - NC
|  ipp_ina_r300_vddio - NC
|  ipp_ina_r300a_vddio - NC
|  ipp_ina_r300b_vddio - NC
|  ipp_ina_r300c_vddio - NC
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Model_type I/O
Polarity   Non-Inverting
Enable   Active-High
Vinl =   0.9900V
Vinh =   2.3100V
Vmeas =  1.6500V
Cref =   30.0000pF
Rref =   1.0000M
Vref =   3.3000V
C_comp   1.3447pF   1.2989pF   1.4124pF
|C_comp_pullup   0.5394pF   0.5687pF   0.5197pF
|C_comp_pulldown   0.7114pF   0.7516pF   0.6815pF
[Model Spec]
| variable   typ   min   max
Vinh   2.3100V   1.8900V   2.5200V
Vinl   0.9900V   0.8100V   1.0800V
[Temperature Range]   25.0000   0.1250k   -40.0000
[Voltage Range]   3.3000V   2.7000V   3.6000V
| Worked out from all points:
|   slope of the pulldown table from 0 to 0.495 V, typ, clamps not added: 40.9 ohm
|   slope of the pullup table from 0 to 0.495 V, typ, clamps not added: 47.8 ohm
|   GND clamp passes 1 mA (typ) near -0.63 V on its own axis
|   POWER clamp passes 1 mA (typ) near -0.62 V on its own axis
|   rising waveform, R_fixture 96.0000, V_fixture 0.0: 20-80 % time 13.3ns typ, 27.9ns min, 8.15ns max; typ from 0 V to 2.08 V
|   rising waveform, R_fixture 96.0000, V_fixture 3.3000: 20-80 % time 452ps typ, 630ps min, 368ps max; typ from 1.09 V to 3.3 V
|   falling waveform, R_fixture 96.0000, V_fixture 0.0: 20-80 % time 425ps typ, 578ps min, 359ps max; typ from 2.08 V to 0 V
|   falling waveform, R_fixture 96.0000, V_fixture 3.3000: 20-80 % time 11.1ns typ, 24.1ns min, 6.7ns max; typ from 3.3 V to 1.09 V
[Pulldown]
|Voltage   I(typ)   I(min)   I(max)
-3.6V     -12.69mA   -13mA      -10.11mA
-2.39V    -11.94mA   -11.39mA   -9.904mA
-1.29V    -18.75mA   -11.81mA   -23.44mA
-960mV    -19.65mA   -12.1mA    -25.03mA
-520mV    -13.48mA   -8.852mA   -17.4mA
800mV     18.2mA     10.89mA    24.65mA
1.35V     26.4mA     15.03mA    36.44mA
1.79V     30.36mA    16.39mA    42.66mA
3V        32.13mA    16.7mA     46.09mA
4.43V     30.32mA    15.91mA    46.39mA
5.31V     30.88mA    16.39mA    43.77mA
7.2V      38.57mA    21.1mA     54.25mA
[Pullup]
|Voltage   I(typ)   I(min)   I(max)
-3.6V     377.7uA    207.8uA    734.8uA
-1.16V    3.397mA    1.602mA    4.185mA
-1.05V    3.926mA    1.816mA    8.675mA
-940mV    10.64mA    2.207mA    21.58mA
-830mV    16.7mA     5.22mA     21.24mA
-720mV    15.83mA    8.86mA     19.49mA
-610mV    14.01mA    9.302mA    17.31mA
820mV     -16.02mA   -10.13mA   -20.77mA
1.48V     -24.67mA   -14.68mA   -32.64mA
2.03V     -28.89mA   -16.19mA   -39.05mA
3.46V     -31.88mA   -16.93mA   -44.52mA
7.2V      -34.49mA   -18.94mA   -47.77mA
[GND_clamp]
|Voltage   I(typ)   I(min)   I(max)
-3.6V     -5.607A    -4.475A    -7.131A
-1.18V    -473.1mA   -501.9mA   -466.9mA
-1.07V    -276.4mA   -353.7mA   -210.9mA
-960mV    -99.46mA   -211.8mA   -30.02mA
-850mV    -10.76mA   -84.44mA   -5.071mA
-740mV    -2.291mA   -13.69mA   -2.754mA
-630mV    -1.016mA   -1.69mA    -1.169mA
-520mV    -314uA     -442.2uA   -284uA
7.2V      0A         0A         0A
[POWER_clamp]
|Voltage   I(typ)   I(min)   I(max)
-3.6V     14.37A     12.86A     16.2A
-1.16V    1.168A     1.525A     943.2mA
-1.05V    594.1mA    1.025A     315.9mA
-940mV    133.7mA    534mA      20.04mA
-830mV    8.718mA    144.9mA    4.268mA
-720mV    2.135mA    15.37mA    2.235mA
-610mV    851.7uA    1.853mA    843.3uA
7.2V      0A         0A         0A
[Ramp]
| variable   typ   min   max
dV/dt_r  1.2493/13.3320n   0.8007/27.8703n   1.5064/8.1523n
dV/dt_f  1.3247/11.0843n   0.8409/24.1308n   1.6023/6.6988n
R_load = 96.0000
[Rising Waveform]
R_fixture= 96.0000
V_fixture= 0.0
V_fixture_min= 0.0
V_fixture_max= 0.0
|time   V(typ)   V(min)   V(max)
0s        3.04nV     105.4nV    10.42nV
6.622ns   -4.393mV   -3.111mV   50.33mV
11.11ns   127mV      -1.772mV   872.1mV
17.13ns   729.8mV    21.93mV    1.956V
20.32ns   1.075V     73.25mV    2.206V
25.23ns   1.518V     197.6mV    2.351V
36.02ns   1.892V     555.6mV    2.459V
48.78ns   2.006V     946.3mV    2.495V
59.99ns   2.046V     1.125V     2.505V
132.1ns   2.082V     1.334V     2.511V
[Rising Waveform]
R_fixture= 96.0000
V_fixture= 3.3000
V_fixture_min= 2.7000
V_fixture_max= 3.6000
|time   V(typ)   V(min)   V(max)
0s        1.092V     1.289V     929.5mV
1.358ns   1.111V     1.289V     1.103V
1.484ns   1.142V     1.288V     1.39V
1.802ns   1.363V     1.29V      2.838V
2.115ns   2.262V     1.331V     3.443V
2.358ns   2.906V     1.406V     3.517V
2.584ns   3.166V     1.573V     3.513V
3.247ns   3.25V      2.451V     3.558V
3.845ns   3.261V     2.67V      3.584V
132.1ns   3.3V       2.7V       3.6V
[Falling Waveform]
R_fixture= 96.0000
V_fixture= 0.0
V_fixture_min= 0.0
V_fixture_max= 0.0
|time   V(typ)   V(min)   V(max)
0s        2.083V     1.349V     2.511V
1.39ns    2.084V     1.349V     2.371V
1.551ns   2.075V     1.349V     2.038V
1.815ns   1.962V     1.348V     862.2mV
1.973ns   1.761V     1.349V     362mV
2.42ns    457.9mV    1.334V     58.72mV
2.777ns   66.33mV    1.208V     54.64mV
3.659ns   36.1mV     133.6mV    40.45mV
4.386ns   32.15mV    10.17mV    26.48mV
132.1ns   450nV      7.08uV     34.03nV
[Falling Waveform]
R_fixture= 96.0000
V_fixture= 3.3000
V_fixture_min= 2.7000
V_fixture_max= 3.6000
|time   V(typ)   V(min)   V(max)
0s        3.3V       2.7V       3.6V
5.751ns   3.284V     2.697V     3.584V
9.477ns   3.044V     2.695V     2.832V
15.55ns   2.276V     2.612V     1.415V
17.86ns   1.988V     2.554V     1.183V
21.7ns    1.575V     2.43V      1.056V
31.41ns   1.241V     2.051V     963.3mV
42.31ns   1.153V     1.66V      939.8mV
53.34ns   1.12V      1.484V     933.2mV
132.1ns   1.092V     1.299V     929.6mV
